VERSION 5.7 ;
  NOWIREEXTENSIONATPIN ON ;
  DIVIDERCHAR "/" ;
  BUSBITCHARS "[]" ;
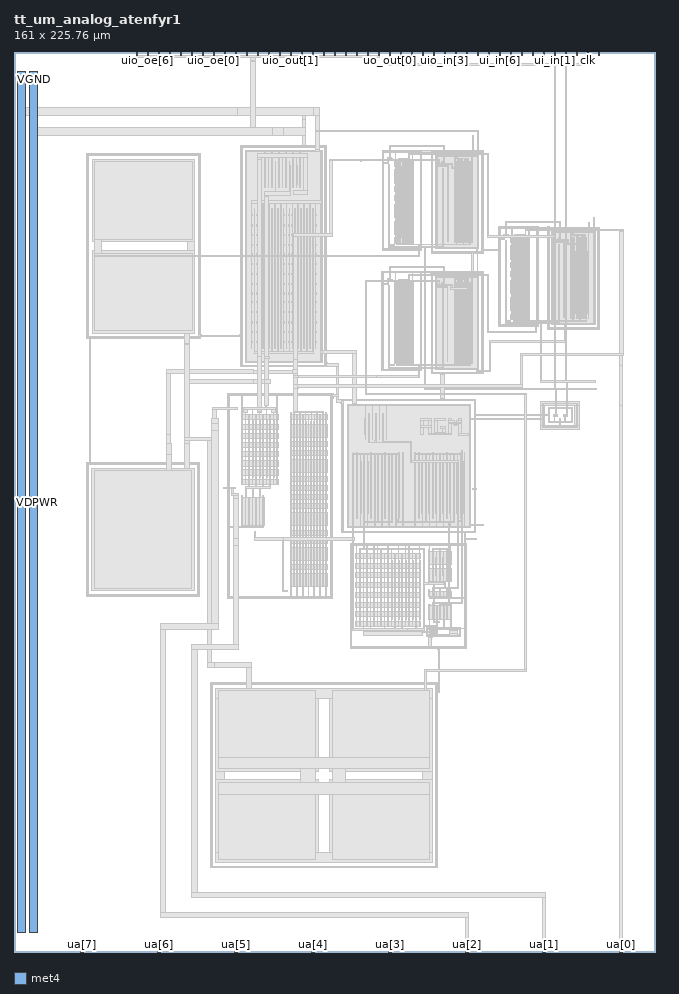
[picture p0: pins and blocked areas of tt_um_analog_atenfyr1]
MACRO tt_um_analog_atenfyr1
  CLASS BLOCK ;
  FOREIGN tt_um_analog_atenfyr1 ;
  ORIGIN 0.000 0.000 ;
  SIZE 161.000 BY 225.760 ;
  PIN VGND
    USE GROUND ;
    PORT
      LAYER met4 ;
        RECT 4.000 5.000 6.000 220.760 ;
    END
  END VGND
  PIN VDPWR
    USE POWER ;
    PORT
      LAYER met4 ;
        RECT 1.000 5.000 3.000 220.760 ;
    END
  END VDPWR
  PIN uo_out[7]
    ANTENNAGATEAREA 107.399994 ;
    ANTENNADIFFAREA 342.756805 ;
    PORT
      LAYER met4 ;
        RECT 74.830 224.760 75.130 225.760 ;
    END
  END uo_out[7]
  PIN uo_out[6]
    ANTENNAGATEAREA 107.399994 ;
    ANTENNADIFFAREA 342.756805 ;
    PORT
      LAYER met4 ;
        RECT 77.590 224.760 77.890 225.760 ;
    END
  END uo_out[6]
  PIN uo_out[5]
    ANTENNAGATEAREA 107.399994 ;
    ANTENNADIFFAREA 342.756805 ;
    PORT
      LAYER met4 ;
        RECT 80.350 224.760 80.650 225.760 ;
    END
  END uo_out[5]
  PIN uo_out[4]
    ANTENNAGATEAREA 107.399994 ;
    ANTENNADIFFAREA 342.756805 ;
    PORT
      LAYER met4 ;
        RECT 83.110 224.760 83.410 225.760 ;
    END
  END uo_out[4]
  PIN uo_out[3]
    ANTENNAGATEAREA 107.399994 ;
    ANTENNADIFFAREA 342.756805 ;
    PORT
      LAYER met4 ;
        RECT 85.870 224.760 86.170 225.760 ;
    END
  END uo_out[3]
  PIN uo_out[2]
    ANTENNAGATEAREA 107.399994 ;
    ANTENNADIFFAREA 342.756805 ;
    PORT
      LAYER met4 ;
        RECT 88.630 224.760 88.930 225.760 ;
    END
  END uo_out[2]
  PIN uo_out[1]
    ANTENNAGATEAREA 107.399994 ;
    ANTENNADIFFAREA 342.756805 ;
    PORT
      LAYER met4 ;
        RECT 91.390 224.760 91.690 225.760 ;
    END
  END uo_out[1]
  PIN uo_out[0]
    PORT
      LAYER met4 ;
        RECT 94.150 224.760 94.450 225.760 ;
    END
  END uo_out[0]
  PIN uio_out[7]
    ANTENNAGATEAREA 107.399994 ;
    ANTENNADIFFAREA 342.756805 ;
    PORT
      LAYER met4 ;
        RECT 52.750 224.760 53.050 225.760 ;
    END
  END uio_out[7]
  PIN uio_out[6]
    ANTENNAGATEAREA 107.399994 ;
    ANTENNADIFFAREA 342.756805 ;
    PORT
      LAYER met4 ;
        RECT 55.510 224.760 55.810 225.760 ;
    END
  END uio_out[6]
  PIN uio_out[5]
    ANTENNAGATEAREA 107.399994 ;
    ANTENNADIFFAREA 342.756805 ;
    PORT
      LAYER met4 ;
        RECT 58.270 224.760 58.570 225.760 ;
    END
  END uio_out[5]
  PIN uio_out[4]
    ANTENNAGATEAREA 107.399994 ;
    ANTENNADIFFAREA 342.756805 ;
    PORT
      LAYER met4 ;
        RECT 61.030 224.760 61.330 225.760 ;
    END
  END uio_out[4]
  PIN uio_out[3]
    ANTENNAGATEAREA 107.399994 ;
    ANTENNADIFFAREA 342.756805 ;
    PORT
      LAYER met4 ;
        RECT 63.790 224.760 64.090 225.760 ;
    END
  END uio_out[3]
  PIN uio_out[2]
    ANTENNAGATEAREA 107.399994 ;
    ANTENNADIFFAREA 342.756805 ;
    PORT
      LAYER met4 ;
        RECT 66.550 224.760 66.850 225.760 ;
    END
  END uio_out[2]
  PIN uio_out[1]
    ANTENNAGATEAREA 107.399994 ;
    ANTENNADIFFAREA 342.756805 ;
    PORT
      LAYER met4 ;
        RECT 69.310 224.760 69.610 225.760 ;
    END
  END uio_out[1]
  PIN uio_out[0]
    ANTENNAGATEAREA 107.399994 ;
    ANTENNADIFFAREA 342.756805 ;
    PORT
      LAYER met4 ;
        RECT 72.070 224.760 72.370 225.760 ;
    END
  END uio_out[0]
  PIN uio_oe[7]
    ANTENNAGATEAREA 107.399994 ;
    ANTENNADIFFAREA 342.756805 ;
    PORT
      LAYER met4 ;
        RECT 30.670 224.760 30.970 225.760 ;
    END
  END uio_oe[7]
  PIN uio_oe[6]
    ANTENNAGATEAREA 107.399994 ;
    ANTENNADIFFAREA 342.756805 ;
    PORT
      LAYER met4 ;
        RECT 33.430 224.760 33.730 225.760 ;
    END
  END uio_oe[6]
  PIN uio_oe[5]
    ANTENNAGATEAREA 107.399994 ;
    ANTENNADIFFAREA 342.756805 ;
    PORT
      LAYER met4 ;
        RECT 36.190 224.760 36.490 225.760 ;
    END
  END uio_oe[5]
  PIN uio_oe[4]
    ANTENNAGATEAREA 107.399994 ;
    ANTENNADIFFAREA 342.756805 ;
    PORT
      LAYER met4 ;
        RECT 38.950 224.760 39.250 225.760 ;
    END
  END uio_oe[4]
  PIN uio_oe[3]
    ANTENNAGATEAREA 107.399994 ;
    ANTENNADIFFAREA 342.756805 ;
    PORT
      LAYER met4 ;
        RECT 41.710 224.760 42.010 225.760 ;
    END
  END uio_oe[3]
  PIN uio_oe[2]
    ANTENNAGATEAREA 107.399994 ;
    ANTENNADIFFAREA 342.756805 ;
    PORT
      LAYER met4 ;
        RECT 44.470 224.760 44.770 225.760 ;
    END
  END uio_oe[2]
  PIN uio_oe[1]
    ANTENNAGATEAREA 107.399994 ;
    ANTENNADIFFAREA 342.756805 ;
    PORT
      LAYER met4 ;
        RECT 47.230 224.760 47.530 225.760 ;
    END
  END uio_oe[1]
  PIN uio_oe[0]
    ANTENNAGATEAREA 107.399994 ;
    ANTENNADIFFAREA 342.756805 ;
    PORT
      LAYER met4 ;
        RECT 49.990 224.760 50.290 225.760 ;
    END
  END uio_oe[0]
  PIN uio_in[7]
    PORT
      LAYER met4 ;
        RECT 96.910 224.760 97.210 225.760 ;
    END
  END uio_in[7]
  PIN uio_in[6]
    PORT
      LAYER met4 ;
        RECT 99.670 224.760 99.970 225.760 ;
    END
  END uio_in[6]
  PIN uio_in[5]
    PORT
      LAYER met4 ;
        RECT 102.430 224.760 102.730 225.760 ;
    END
  END uio_in[5]
  PIN uio_in[4]
    PORT
      LAYER met4 ;
        RECT 105.190 224.760 105.490 225.760 ;
    END
  END uio_in[4]
  PIN uio_in[3]
    PORT
      LAYER met4 ;
        RECT 107.950 224.760 108.250 225.760 ;
    END
  END uio_in[3]
  PIN uio_in[2]
    PORT
      LAYER met4 ;
        RECT 110.710 224.760 111.010 225.760 ;
    END
  END uio_in[2]
  PIN uio_in[1]
    PORT
      LAYER met4 ;
        RECT 113.470 224.760 113.770 225.760 ;
    END
  END uio_in[1]
  PIN uio_in[0]
    PORT
      LAYER met4 ;
        RECT 116.230 224.760 116.530 225.760 ;
    END
  END uio_in[0]
  PIN ui_in[7]
    PORT
      LAYER met4 ;
        RECT 118.990 224.760 119.290 225.760 ;
    END
  END ui_in[7]
  PIN ui_in[6]
    PORT
      LAYER met4 ;
        RECT 121.750 224.760 122.050 225.760 ;
    END
  END ui_in[6]
  PIN ui_in[5]
    PORT
      LAYER met4 ;
        RECT 124.510 224.760 124.810 225.760 ;
    END
  END ui_in[5]
  PIN ui_in[4]
    PORT
      LAYER met4 ;
        RECT 127.270 224.760 127.570 225.760 ;
    END
  END ui_in[4]
  PIN ui_in[3]
    PORT
      LAYER met4 ;
        RECT 130.030 224.760 130.330 225.760 ;
    END
  END ui_in[3]
  PIN ui_in[2]
    PORT
      LAYER met4 ;
        RECT 132.790 224.760 133.090 225.760 ;
    END
  END ui_in[2]
  PIN ui_in[1]
    ANTENNAGATEAREA 24.449999 ;
    ANTENNADIFFAREA 0.111300 ;
    PORT
      LAYER met4 ;
        RECT 135.550 224.760 135.850 225.760 ;
    END
  END ui_in[1]
  PIN ui_in[0]
    ANTENNAGATEAREA 12.224999 ;
    ANTENNADIFFAREA 0.111300 ;
    PORT
      LAYER met4 ;
        RECT 138.310 224.760 138.610 225.760 ;
    END
  END ui_in[0]
  PIN ua[7]
    PORT
      LAYER met4 ;
        RECT 16.570 0.000 17.470 1.000 ;
    END
  END ua[7]
  PIN ua[6]
    PORT
      LAYER met4 ;
        RECT 35.890 0.000 36.790 1.000 ;
    END
  END ua[6]
  PIN ua[5]
    PORT
      LAYER met4 ;
        RECT 55.210 0.000 56.110 1.000 ;
    END
  END ua[5]
  PIN ua[4]
    PORT
      LAYER met4 ;
        RECT 74.530 0.000 75.430 1.000 ;
    END
  END ua[4]
  PIN ua[3]
    PORT
      LAYER met4 ;
        RECT 93.850 0.000 94.750 1.000 ;
    END
  END ua[3]
  PIN ua[2]
    ANTENNAGATEAREA 19.199999 ;
    PORT
      LAYER met4 ;
        RECT 113.170 0.000 114.070 1.000 ;
    END
  END ua[2]
  PIN ua[1]
    ANTENNAGATEAREA 19.199999 ;
    PORT
      LAYER met4 ;
        RECT 132.490 0.000 133.390 1.000 ;
    END
  END ua[1]
  PIN ua[0]
    ANTENNADIFFAREA 130.199997 ;
    PORT
      LAYER met4 ;
        RECT 151.810 0.000 152.710 1.000 ;
    END
  END ua[0]
  PIN rst_n
    PORT
      LAYER met4 ;
        RECT 141.070 224.760 141.370 225.760 ;
    END
  END rst_n
  PIN ena
    PORT
      LAYER met4 ;
        RECT 146.590 224.760 146.890 225.760 ;
    END
  END ena
  PIN clk
    PORT
      LAYER met4 ;
        RECT 143.830 224.760 144.130 225.760 ;
    END
  END clk
  OBS
      LAYER pwell ;
        RECT 56.830 201.780 78.440 202.210 ;
        RECT 18.290 199.780 46.690 200.210 ;
        RECT 18.290 154.280 18.720 199.780 ;
        RECT 46.260 154.280 46.690 199.780 ;
        RECT 18.290 153.850 46.690 154.280 ;
        RECT 56.830 147.185 57.260 201.780 ;
      LAYER nwell ;
        RECT 57.950 147.875 77.320 201.090 ;
      LAYER pwell ;
        RECT 78.010 147.185 78.440 201.780 ;
        RECT 92.320 200.675 102.310 201.105 ;
        RECT 92.320 176.495 92.750 200.675 ;
        RECT 93.630 198.420 94.570 199.180 ;
        RECT 95.440 197.105 100.250 198.365 ;
        RECT 95.440 192.865 100.250 196.215 ;
        RECT 95.440 190.715 100.250 191.975 ;
        RECT 95.440 188.480 100.250 189.740 ;
        RECT 95.440 184.240 100.250 187.590 ;
        RECT 95.440 179.995 100.250 183.350 ;
        RECT 95.440 177.845 100.250 179.105 ;
        RECT 101.880 176.495 102.310 200.675 ;
        RECT 92.320 176.065 102.310 176.495 ;
        RECT 104.640 200.505 117.665 200.935 ;
        RECT 104.640 175.740 105.070 200.505 ;
      LAYER nwell ;
        RECT 105.760 176.430 116.565 199.815 ;
      LAYER pwell ;
        RECT 117.235 175.740 117.665 200.505 ;
        RECT 104.640 175.310 117.665 175.740 ;
        RECT 121.500 181.570 131.490 182.000 ;
        RECT 56.830 146.755 78.440 147.185 ;
        RECT 92.310 170.360 102.300 170.790 ;
        RECT 92.310 146.180 92.740 170.360 ;
        RECT 93.620 168.105 94.560 168.865 ;
        RECT 95.430 166.790 100.240 168.050 ;
        RECT 95.430 162.550 100.240 165.900 ;
        RECT 95.430 160.400 100.240 161.660 ;
        RECT 95.430 158.165 100.240 159.425 ;
        RECT 95.430 153.925 100.240 157.275 ;
        RECT 95.430 149.680 100.240 153.035 ;
        RECT 95.430 147.530 100.240 148.790 ;
        RECT 101.870 146.180 102.300 170.360 ;
        RECT 92.310 145.750 102.300 146.180 ;
        RECT 104.630 170.190 117.655 170.620 ;
        RECT 104.630 145.425 105.060 170.190 ;
      LAYER nwell ;
        RECT 105.750 146.115 116.555 169.500 ;
      LAYER pwell ;
        RECT 117.225 145.425 117.655 170.190 ;
        RECT 121.500 157.390 121.930 181.570 ;
        RECT 122.810 179.315 123.750 180.075 ;
        RECT 124.620 178.000 129.430 179.260 ;
        RECT 124.620 173.760 129.430 177.110 ;
        RECT 124.620 171.610 129.430 172.870 ;
        RECT 124.620 169.375 129.430 170.635 ;
        RECT 124.620 165.135 129.430 168.485 ;
        RECT 124.620 160.890 129.430 164.245 ;
        RECT 124.620 158.740 129.430 160.000 ;
        RECT 131.060 157.390 131.490 181.570 ;
        RECT 121.500 156.960 131.490 157.390 ;
        RECT 133.820 181.400 146.845 181.830 ;
        RECT 133.820 156.635 134.250 181.400 ;
      LAYER nwell ;
        RECT 134.940 157.325 145.745 180.710 ;
      LAYER pwell ;
        RECT 146.415 156.635 146.845 181.400 ;
        RECT 133.820 156.205 146.845 156.635 ;
        RECT 104.630 144.995 117.655 145.425 ;
        RECT 53.600 139.680 79.890 140.110 ;
        RECT 18.160 122.250 46.560 122.680 ;
        RECT 18.160 89.710 18.590 122.250 ;
        RECT 46.130 89.710 46.560 122.250 ;
        RECT 18.160 89.280 46.560 89.710 ;
        RECT 53.600 89.180 54.030 139.680 ;
        RECT 56.945 133.460 66.255 134.720 ;
        RECT 69.245 133.460 78.515 134.720 ;
        RECT 56.945 131.160 66.255 132.420 ;
        RECT 56.945 128.905 66.255 130.165 ;
        RECT 69.245 129.095 78.515 132.410 ;
        RECT 56.945 126.605 66.255 127.865 ;
        RECT 69.245 126.785 78.515 128.045 ;
        RECT 56.945 124.205 66.255 125.465 ;
        RECT 69.245 124.555 78.515 125.815 ;
        RECT 56.945 121.905 66.255 123.165 ;
        RECT 56.945 119.650 66.255 120.910 ;
        RECT 69.245 120.345 78.515 123.660 ;
        RECT 56.945 117.350 66.255 118.610 ;
        RECT 69.245 118.035 78.515 119.295 ;
        RECT 69.245 115.845 78.515 117.105 ;
        RECT 56.955 106.985 62.745 114.000 ;
        RECT 69.245 113.585 78.515 114.845 ;
        RECT 69.245 111.250 78.515 112.510 ;
        RECT 69.245 106.885 78.515 110.200 ;
        RECT 69.245 104.575 78.515 105.835 ;
        RECT 69.245 102.345 78.515 103.605 ;
        RECT 69.245 98.135 78.515 101.450 ;
        RECT 69.245 95.825 78.515 97.085 ;
        RECT 69.245 91.590 78.515 94.895 ;
        RECT 79.460 89.180 79.890 139.680 ;
        RECT 82.235 138.270 115.850 138.700 ;
        RECT 82.235 105.545 82.665 138.270 ;
      LAYER nwell ;
        RECT 83.535 106.415 114.550 137.400 ;
      LAYER pwell ;
        RECT 115.420 105.545 115.850 138.270 ;
      LAYER nwell ;
        RECT 132.015 137.130 141.815 138.190 ;
        RECT 132.015 132.190 133.105 137.130 ;
      LAYER pwell ;
        RECT 134.020 136.240 140.190 136.670 ;
        RECT 134.020 133.140 134.450 136.240 ;
        RECT 135.330 134.270 136.270 134.950 ;
        RECT 137.940 134.270 138.880 134.950 ;
        RECT 139.760 133.140 140.190 136.240 ;
        RECT 134.020 132.710 140.190 133.140 ;
      LAYER nwell ;
        RECT 140.705 132.190 141.815 137.130 ;
        RECT 132.015 131.130 141.815 132.190 ;
      LAYER pwell ;
        RECT 82.235 105.115 115.850 105.545 ;
        RECT 53.600 88.750 79.890 89.180 ;
        RECT 84.340 101.925 113.400 102.355 ;
        RECT 84.340 76.675 84.770 101.925 ;
        RECT 85.650 98.605 102.000 99.865 ;
        RECT 85.650 96.180 102.000 97.440 ;
        RECT 103.945 97.090 109.735 100.450 ;
        RECT 85.650 93.845 102.000 95.105 ;
        RECT 103.945 92.855 109.735 96.215 ;
        RECT 85.650 91.420 102.000 92.680 ;
        RECT 85.650 88.895 102.000 90.155 ;
        RECT 103.945 89.070 109.735 90.330 ;
        RECT 85.650 86.470 102.000 87.730 ;
        RECT 85.650 84.135 102.000 85.395 ;
        RECT 104.010 83.455 109.800 86.815 ;
        RECT 85.650 81.710 102.000 82.970 ;
        RECT 103.385 80.955 112.105 81.385 ;
        RECT 103.385 79.565 103.815 80.955 ;
        RECT 111.675 79.565 112.105 80.955 ;
        RECT 103.385 79.135 112.105 79.565 ;
        RECT 112.970 76.675 113.400 101.925 ;
        RECT 84.340 76.245 113.400 76.675 ;
        RECT 49.260 67.060 106.270 67.490 ;
        RECT 49.260 21.560 49.690 67.060 ;
        RECT 105.840 21.560 106.270 67.060 ;
        RECT 49.260 21.130 106.270 21.560 ;
      LAYER li1 ;
        RECT 72.295 202.080 73.215 202.730 ;
        RECT 56.960 201.910 78.310 202.080 ;
        RECT 18.420 199.910 46.560 200.080 ;
        RECT 18.420 154.150 18.590 199.910 ;
        RECT 46.390 154.790 46.560 199.910 ;
        RECT 56.960 154.790 57.130 201.910 ;
        RECT 75.680 200.910 76.570 201.550 ;
        RECT 46.390 154.460 46.950 154.790 ;
        RECT 56.585 154.460 57.130 154.790 ;
        RECT 46.390 154.150 46.560 154.460 ;
        RECT 18.420 153.980 46.560 154.150 ;
        RECT 18.970 153.475 19.300 153.980 ;
        RECT 56.960 147.055 57.130 154.460 ;
        RECT 58.130 200.740 77.140 200.910 ;
        RECT 58.130 148.225 58.300 200.740 ;
        RECT 62.875 191.690 63.045 200.740 ;
        RECT 63.395 199.240 64.285 199.570 ;
        RECT 63.755 191.690 63.925 199.240 ;
        RECT 64.635 191.690 64.805 200.740 ;
        RECT 65.515 191.690 65.685 198.175 ;
        RECT 66.395 191.690 66.565 200.740 ;
        RECT 66.915 199.240 67.805 199.570 ;
        RECT 67.275 191.690 67.445 199.240 ;
        RECT 68.155 191.690 68.325 200.740 ;
        RECT 69.035 191.690 69.205 198.175 ;
        RECT 69.915 191.690 70.085 200.740 ;
        RECT 70.435 199.240 71.325 199.570 ;
        RECT 70.795 191.690 70.965 199.240 ;
        RECT 71.675 191.690 71.845 200.740 ;
        RECT 70.150 189.930 70.320 190.980 ;
        RECT 76.970 188.485 77.140 200.740 ;
        RECT 59.520 187.705 77.140 188.485 ;
        RECT 59.520 151.455 59.690 187.705 ;
        RECT 60.250 150.685 60.420 186.510 ;
        RECT 60.980 151.455 61.150 187.705 ;
        RECT 61.710 150.685 61.880 186.510 ;
        RECT 62.440 151.455 62.610 187.705 ;
        RECT 63.170 150.685 63.340 186.510 ;
        RECT 63.900 151.455 64.070 187.705 ;
        RECT 64.630 150.685 64.800 186.510 ;
        RECT 65.360 151.455 65.530 187.705 ;
        RECT 66.090 150.685 66.260 186.510 ;
        RECT 66.820 151.455 66.990 187.705 ;
        RECT 67.550 150.685 67.720 186.510 ;
        RECT 68.280 151.455 68.450 187.705 ;
        RECT 69.010 150.685 69.180 186.510 ;
        RECT 69.740 151.455 69.910 187.705 ;
        RECT 70.470 150.685 70.640 186.510 ;
        RECT 71.200 151.455 71.370 187.705 ;
        RECT 71.930 150.685 72.100 186.510 ;
        RECT 72.660 151.455 72.830 187.705 ;
        RECT 73.390 150.685 73.560 186.510 ;
        RECT 74.120 151.455 74.290 187.705 ;
        RECT 74.850 150.685 75.020 186.510 ;
        RECT 75.580 151.455 75.750 187.705 ;
        RECT 60.250 150.015 75.020 150.685 ;
        RECT 76.970 150.930 77.140 187.705 ;
        RECT 76.970 150.040 77.715 150.930 ;
        RECT 63.930 148.915 64.100 149.245 ;
        RECT 70.145 149.225 71.160 150.015 ;
        RECT 76.970 148.225 77.140 150.040 ;
        RECT 58.130 148.055 77.140 148.225 ;
        RECT 78.140 147.970 78.310 201.910 ;
        RECT 92.450 200.805 102.390 200.975 ;
        RECT 92.450 198.025 92.620 200.805 ;
        RECT 94.230 199.050 94.400 199.570 ;
        RECT 93.800 198.025 93.970 199.050 ;
        RECT 94.230 198.880 94.980 199.050 ;
        RECT 94.230 198.550 94.400 198.880 ;
        RECT 92.450 197.820 93.970 198.025 ;
        RECT 92.450 176.365 92.620 197.820 ;
        RECT 94.075 197.170 94.245 197.500 ;
        RECT 95.610 177.975 95.780 200.805 ;
        RECT 99.050 199.120 99.220 199.495 ;
        RECT 96.470 198.940 99.220 199.120 ;
        RECT 96.040 177.580 96.210 198.235 ;
        RECT 96.470 177.975 96.640 198.940 ;
        RECT 96.900 177.975 97.070 198.745 ;
        RECT 97.330 177.975 97.500 198.940 ;
        RECT 97.760 177.580 97.930 198.235 ;
        RECT 98.190 177.975 98.360 198.940 ;
        RECT 98.620 177.975 98.790 198.745 ;
        RECT 99.050 177.975 99.220 198.940 ;
        RECT 99.480 177.580 99.650 198.235 ;
        RECT 99.910 177.975 100.080 200.805 ;
        RECT 102.010 200.645 102.390 200.805 ;
        RECT 104.560 200.805 105.060 200.975 ;
        RECT 115.015 200.805 115.185 201.445 ;
        RECT 95.060 177.375 95.390 177.545 ;
        RECT 96.040 177.365 101.525 177.580 ;
        RECT 102.010 176.365 102.180 200.645 ;
        RECT 104.560 200.635 117.535 200.805 ;
        RECT 92.450 176.195 102.180 176.365 ;
        RECT 104.770 175.610 104.940 200.635 ;
        RECT 106.275 200.135 109.055 200.305 ;
        RECT 116.195 199.635 116.365 200.220 ;
        RECT 105.940 199.465 116.365 199.635 ;
        RECT 105.940 197.285 106.110 199.465 ;
        RECT 107.330 197.285 107.500 198.285 ;
        RECT 105.940 197.105 107.500 197.285 ;
        RECT 107.760 197.285 107.930 198.770 ;
        RECT 105.940 176.780 106.110 197.105 ;
        RECT 107.760 197.055 108.845 197.285 ;
        RECT 108.675 196.955 108.845 197.055 ;
        RECT 107.550 196.295 107.720 196.625 ;
        RECT 108.675 178.350 108.845 178.680 ;
        RECT 110.505 177.960 110.675 199.465 ;
        RECT 110.925 198.955 114.115 199.140 ;
        RECT 110.935 177.580 111.105 198.235 ;
        RECT 111.365 177.960 111.535 198.955 ;
        RECT 111.795 177.960 111.965 198.745 ;
        RECT 112.225 177.960 112.395 198.955 ;
        RECT 112.655 177.580 112.825 198.235 ;
        RECT 113.085 177.960 113.255 198.955 ;
        RECT 113.515 177.960 113.690 198.745 ;
        RECT 113.945 177.960 114.115 198.955 ;
        RECT 114.375 177.580 114.545 198.235 ;
        RECT 114.805 177.960 114.975 199.465 ;
        RECT 106.820 177.365 114.545 177.580 ;
        RECT 116.195 176.780 116.365 199.465 ;
        RECT 105.940 176.610 116.365 176.780 ;
        RECT 116.075 176.350 116.245 176.610 ;
        RECT 117.365 176.285 117.535 200.635 ;
        RECT 121.630 181.700 131.570 181.870 ;
        RECT 121.630 178.920 121.800 181.700 ;
        RECT 123.410 179.945 123.580 180.465 ;
        RECT 122.980 178.920 123.150 179.945 ;
        RECT 123.410 179.775 124.160 179.945 ;
        RECT 123.410 179.445 123.580 179.775 ;
        RECT 121.630 178.715 123.150 178.920 ;
        RECT 121.630 176.310 121.800 178.715 ;
        RECT 123.255 178.065 123.425 178.395 ;
        RECT 117.365 175.955 117.705 176.285 ;
        RECT 121.460 175.980 121.800 176.310 ;
        RECT 109.810 175.610 110.700 175.815 ;
        RECT 117.365 175.610 117.535 175.955 ;
        RECT 104.770 175.440 117.535 175.610 ;
        RECT 114.865 175.035 115.035 175.440 ;
        RECT 92.440 170.490 102.380 170.660 ;
        RECT 92.440 167.710 92.610 170.490 ;
        RECT 94.220 168.735 94.390 169.255 ;
        RECT 93.790 167.710 93.960 168.735 ;
        RECT 94.220 168.565 94.970 168.735 ;
        RECT 94.220 168.235 94.390 168.565 ;
        RECT 92.440 167.505 93.960 167.710 ;
        RECT 78.140 147.055 78.645 147.970 ;
        RECT 56.960 146.920 78.645 147.055 ;
        RECT 56.960 146.885 78.310 146.920 ;
        RECT 92.440 146.050 92.610 167.505 ;
        RECT 94.065 166.855 94.235 167.185 ;
        RECT 95.600 147.660 95.770 170.490 ;
        RECT 99.040 168.805 99.210 169.180 ;
        RECT 96.460 168.625 99.210 168.805 ;
        RECT 96.030 147.265 96.200 167.920 ;
        RECT 96.460 147.660 96.630 168.625 ;
        RECT 96.890 147.660 97.060 168.430 ;
        RECT 97.320 147.660 97.490 168.625 ;
        RECT 97.750 147.265 97.920 167.920 ;
        RECT 98.180 147.660 98.350 168.625 ;
        RECT 98.610 147.660 98.780 168.430 ;
        RECT 99.040 147.660 99.210 168.625 ;
        RECT 99.470 147.265 99.640 167.920 ;
        RECT 99.900 147.660 100.070 170.490 ;
        RECT 102.000 170.330 102.380 170.490 ;
        RECT 104.550 170.490 105.050 170.660 ;
        RECT 115.005 170.490 115.175 171.130 ;
        RECT 95.050 147.060 95.380 147.230 ;
        RECT 96.030 147.050 101.515 147.265 ;
        RECT 102.000 146.050 102.170 170.330 ;
        RECT 104.550 170.320 117.525 170.490 ;
        RECT 59.705 145.100 70.110 145.990 ;
        RECT 92.440 145.880 102.170 146.050 ;
        RECT 104.760 145.295 104.930 170.320 ;
        RECT 106.265 169.820 109.045 169.990 ;
        RECT 116.185 169.320 116.355 169.905 ;
        RECT 105.930 169.150 116.355 169.320 ;
        RECT 105.930 166.970 106.100 169.150 ;
        RECT 107.320 166.970 107.490 167.970 ;
        RECT 105.930 166.790 107.490 166.970 ;
        RECT 107.750 166.970 107.920 168.455 ;
        RECT 105.930 146.465 106.100 166.790 ;
        RECT 107.750 166.740 108.835 166.970 ;
        RECT 108.665 166.640 108.835 166.740 ;
        RECT 107.540 165.980 107.710 166.310 ;
        RECT 108.665 148.035 108.835 148.365 ;
        RECT 110.495 147.645 110.665 169.150 ;
        RECT 110.915 168.640 114.105 168.825 ;
        RECT 110.925 147.265 111.095 167.920 ;
        RECT 111.355 147.645 111.525 168.640 ;
        RECT 111.785 147.645 111.955 168.430 ;
        RECT 112.215 147.645 112.385 168.640 ;
        RECT 112.645 147.265 112.815 167.920 ;
        RECT 113.075 147.645 113.245 168.640 ;
        RECT 113.505 147.645 113.680 168.430 ;
        RECT 113.935 147.645 114.105 168.640 ;
        RECT 114.365 147.265 114.535 167.920 ;
        RECT 114.795 147.645 114.965 169.150 ;
        RECT 106.810 147.050 114.535 147.265 ;
        RECT 116.185 146.465 116.355 169.150 ;
        RECT 105.930 146.295 116.355 146.465 ;
        RECT 116.065 145.995 116.235 146.295 ;
        RECT 117.355 145.295 117.525 170.320 ;
        RECT 121.630 157.260 121.800 175.980 ;
        RECT 124.790 158.870 124.960 181.700 ;
        RECT 128.230 180.015 128.400 180.390 ;
        RECT 125.650 179.835 128.400 180.015 ;
        RECT 125.220 158.475 125.390 179.130 ;
        RECT 125.650 158.870 125.820 179.835 ;
        RECT 126.080 158.870 126.250 179.640 ;
        RECT 126.510 158.870 126.680 179.835 ;
        RECT 126.940 158.475 127.110 179.130 ;
        RECT 127.370 158.870 127.540 179.835 ;
        RECT 127.800 158.870 127.970 179.640 ;
        RECT 128.230 158.870 128.400 179.835 ;
        RECT 128.660 158.475 128.830 179.130 ;
        RECT 129.090 158.870 129.260 181.700 ;
        RECT 131.190 181.540 131.570 181.700 ;
        RECT 133.740 181.700 134.240 181.870 ;
        RECT 144.195 181.700 144.365 182.340 ;
        RECT 124.240 158.270 124.570 158.440 ;
        RECT 125.220 158.260 130.705 158.475 ;
        RECT 131.190 157.260 131.360 181.540 ;
        RECT 133.740 181.530 146.715 181.700 ;
        RECT 121.630 157.090 131.360 157.260 ;
        RECT 133.950 156.505 134.120 181.530 ;
        RECT 135.455 181.030 138.235 181.200 ;
        RECT 145.375 180.530 145.545 181.115 ;
        RECT 135.120 180.360 145.545 180.530 ;
        RECT 135.120 178.180 135.290 180.360 ;
        RECT 136.510 178.180 136.680 179.180 ;
        RECT 135.120 178.000 136.680 178.180 ;
        RECT 136.940 178.180 137.110 179.665 ;
        RECT 135.120 157.675 135.290 178.000 ;
        RECT 136.940 177.950 138.025 178.180 ;
        RECT 137.855 177.850 138.025 177.950 ;
        RECT 136.730 177.190 136.900 177.520 ;
        RECT 137.855 159.245 138.025 159.575 ;
        RECT 139.685 158.855 139.855 180.360 ;
        RECT 140.105 179.850 143.295 180.035 ;
        RECT 140.115 158.475 140.285 179.130 ;
        RECT 140.545 158.855 140.715 179.850 ;
        RECT 140.975 158.855 141.145 179.640 ;
        RECT 141.405 158.855 141.575 179.850 ;
        RECT 141.835 158.475 142.005 179.130 ;
        RECT 142.265 158.855 142.435 179.850 ;
        RECT 142.695 158.855 142.870 179.640 ;
        RECT 143.125 158.855 143.295 179.850 ;
        RECT 143.555 158.475 143.725 179.130 ;
        RECT 143.985 158.855 144.155 180.360 ;
        RECT 136.000 158.260 143.725 158.475 ;
        RECT 145.375 157.675 145.545 180.360 ;
        RECT 135.120 157.505 145.545 157.675 ;
        RECT 138.115 157.175 138.285 157.505 ;
        RECT 146.545 156.505 146.715 181.530 ;
        RECT 133.950 156.335 146.715 156.505 ;
        RECT 104.760 145.125 117.525 145.295 ;
        RECT 107.095 144.535 107.985 145.125 ;
        RECT 59.705 142.530 64.310 143.500 ;
        RECT 105.630 141.095 109.070 141.425 ;
        RECT 53.730 139.810 80.100 139.980 ;
        RECT 138.510 139.890 138.740 142.485 ;
        RECT 18.970 122.550 19.300 122.980 ;
        RECT 18.290 122.380 46.430 122.550 ;
        RECT 18.290 89.580 18.460 122.380 ;
        RECT 46.260 89.580 46.430 122.380 ;
        RECT 18.290 89.410 46.430 89.580 ;
        RECT 53.730 106.840 53.900 139.810 ;
        RECT 55.740 136.140 55.910 136.470 ;
        RECT 57.115 117.480 57.285 139.810 ;
        RECT 62.895 136.975 63.785 137.305 ;
        RECT 63.210 136.350 63.445 136.975 ;
        RECT 59.755 136.100 63.445 136.350 ;
        RECT 57.635 135.370 58.525 135.700 ;
        RECT 57.995 117.480 58.165 135.370 ;
        RECT 58.875 117.480 59.045 134.590 ;
        RECT 59.755 117.480 59.925 136.100 ;
        RECT 61.155 135.370 62.045 135.700 ;
        RECT 60.635 117.480 60.805 134.590 ;
        RECT 61.515 117.480 61.685 135.370 ;
        RECT 62.395 117.480 62.565 134.590 ;
        RECT 63.275 117.480 63.445 136.100 ;
        RECT 64.675 135.370 65.565 135.700 ;
        RECT 64.155 117.480 64.325 134.590 ;
        RECT 65.035 117.480 65.205 135.370 ;
        RECT 65.915 117.480 66.085 139.810 ;
        RECT 79.590 139.300 80.100 139.810 ;
        RECT 70.145 135.505 71.160 135.940 ;
        RECT 70.145 135.330 77.615 135.505 ;
        RECT 55.460 116.305 55.630 116.635 ;
        RECT 53.730 106.510 54.360 106.840 ;
        RECT 57.125 106.510 57.295 114.480 ;
        RECT 58.005 107.115 58.175 114.615 ;
        RECT 58.885 106.510 59.055 113.870 ;
        RECT 59.765 107.115 59.935 114.615 ;
        RECT 60.645 106.510 60.815 113.870 ;
        RECT 61.525 107.115 61.695 114.615 ;
        RECT 62.405 106.510 62.575 114.480 ;
        RECT 53.730 89.050 53.900 106.510 ;
        RECT 60.325 105.165 60.495 105.495 ;
        RECT 69.415 91.720 69.585 135.220 ;
        RECT 70.145 91.720 70.315 135.330 ;
        RECT 70.875 91.720 71.045 134.590 ;
        RECT 71.605 91.720 71.775 135.330 ;
        RECT 72.335 91.720 72.505 134.590 ;
        RECT 73.065 91.720 73.235 135.330 ;
        RECT 73.795 91.720 73.965 134.590 ;
        RECT 74.525 91.720 74.695 135.330 ;
        RECT 75.255 91.720 75.425 134.590 ;
        RECT 75.985 91.720 76.155 135.330 ;
        RECT 76.715 91.720 76.885 134.590 ;
        RECT 77.445 91.720 77.615 135.330 ;
        RECT 78.175 91.720 78.345 135.220 ;
        RECT 68.240 90.375 68.410 90.705 ;
        RECT 69.385 89.050 69.615 89.975 ;
        RECT 70.845 89.050 71.075 89.975 ;
        RECT 72.305 89.050 72.535 89.975 ;
        RECT 73.765 89.050 73.995 89.975 ;
        RECT 75.225 89.050 75.455 89.975 ;
        RECT 76.685 89.050 76.915 89.975 ;
        RECT 78.145 89.050 78.375 89.975 ;
        RECT 79.590 89.050 79.760 139.300 ;
        RECT 79.930 138.930 80.100 139.300 ;
        RECT 107.095 138.570 107.985 139.120 ;
        RECT 82.015 138.400 115.720 138.570 ;
        RECT 82.015 137.520 82.535 138.400 ;
        RECT 82.365 105.415 82.535 137.520 ;
        RECT 85.040 137.220 85.930 137.900 ;
        RECT 83.715 137.050 114.370 137.220 ;
        RECT 83.715 106.765 83.885 137.050 ;
        RECT 88.075 128.480 88.245 137.050 ;
        RECT 88.955 127.915 89.125 135.205 ;
        RECT 89.835 128.480 90.005 137.050 ;
        RECT 90.715 128.245 90.885 135.205 ;
        RECT 91.595 128.480 91.765 137.050 ;
        RECT 90.490 127.915 90.885 128.245 ;
        RECT 92.475 127.915 92.645 135.205 ;
        RECT 93.355 128.480 93.525 137.050 ;
        RECT 114.200 133.865 114.370 137.050 ;
        RECT 115.550 134.915 115.720 138.400 ;
        RECT 132.540 137.540 141.230 137.710 ;
        RECT 115.550 134.585 116.190 134.915 ;
        RECT 114.200 133.535 114.795 133.865 ;
        RECT 114.200 129.955 114.370 133.535 ;
        RECT 113.735 129.625 114.370 129.955 ;
        RECT 88.955 127.725 93.210 127.915 ;
        RECT 85.105 106.765 85.275 125.290 ;
        RECT 85.985 108.620 86.155 125.185 ;
        RECT 86.865 106.765 87.035 124.440 ;
        RECT 87.745 107.695 87.915 124.440 ;
        RECT 88.625 106.765 88.795 124.440 ;
        RECT 89.505 108.620 89.675 125.185 ;
        RECT 90.385 106.765 90.555 124.440 ;
        RECT 91.265 107.695 91.435 124.440 ;
        RECT 92.145 106.765 92.315 124.440 ;
        RECT 93.025 108.620 93.195 125.185 ;
        RECT 93.905 106.765 94.075 124.440 ;
        RECT 94.785 107.695 94.955 124.440 ;
        RECT 95.665 106.765 95.835 124.440 ;
        RECT 96.545 108.620 96.715 125.185 ;
        RECT 96.240 108.105 96.410 108.435 ;
        RECT 97.425 106.765 97.595 125.290 ;
        RECT 100.585 106.765 100.755 125.290 ;
        RECT 101.465 108.620 101.635 125.185 ;
        RECT 102.345 106.765 102.515 124.440 ;
        RECT 103.225 107.695 103.395 124.440 ;
        RECT 104.105 106.765 104.275 124.440 ;
        RECT 104.985 108.620 105.155 125.185 ;
        RECT 105.865 106.765 106.035 124.440 ;
        RECT 106.745 107.695 106.915 124.440 ;
        RECT 107.625 106.765 107.795 124.440 ;
        RECT 108.505 108.620 108.675 125.185 ;
        RECT 109.385 106.765 109.555 124.440 ;
        RECT 110.265 107.695 110.435 124.440 ;
        RECT 111.145 106.765 111.315 124.440 ;
        RECT 112.025 108.620 112.195 125.185 ;
        RECT 111.725 108.015 111.895 108.345 ;
        RECT 112.905 106.765 113.075 125.290 ;
        RECT 114.200 107.145 114.370 129.625 ;
        RECT 115.550 116.315 115.720 134.585 ;
        RECT 132.540 133.865 132.710 137.540 ;
        RECT 134.150 136.370 140.060 136.540 ;
        RECT 134.150 134.915 134.320 136.370 ;
        RECT 133.740 134.585 134.320 134.915 ;
        RECT 132.110 133.535 132.710 133.865 ;
        RECT 132.540 131.840 132.710 133.535 ;
        RECT 134.150 133.010 134.320 134.585 ;
        RECT 135.500 133.010 135.670 134.820 ;
        RECT 135.930 134.400 136.100 135.370 ;
        RECT 136.805 133.470 136.975 133.800 ;
        RECT 138.110 133.010 138.280 134.820 ;
        RECT 138.540 134.400 138.710 135.370 ;
        RECT 139.890 133.010 140.060 136.370 ;
        RECT 134.150 132.840 140.060 133.010 ;
        RECT 136.735 131.840 137.065 132.430 ;
        RECT 141.060 131.840 141.230 137.540 ;
        RECT 132.540 131.670 141.230 131.840 ;
        RECT 115.045 115.985 115.935 116.315 ;
        RECT 114.200 106.915 114.840 107.145 ;
        RECT 114.200 106.765 114.370 106.915 ;
        RECT 83.715 106.595 114.370 106.765 ;
        RECT 115.550 105.415 115.720 115.985 ;
        RECT 82.365 105.245 115.720 105.415 ;
        RECT 112.995 104.915 113.225 105.245 ;
        RECT 112.995 102.225 113.230 102.555 ;
        RECT 53.730 88.880 79.760 89.050 ;
        RECT 84.470 102.055 113.270 102.225 ;
        RECT 84.470 76.545 84.640 102.055 ;
        RECT 85.820 81.840 85.990 102.055 ;
        RECT 86.700 81.840 86.870 101.210 ;
        RECT 87.580 80.315 87.750 99.735 ;
        RECT 88.460 81.840 88.630 102.055 ;
        RECT 89.340 81.085 89.510 99.735 ;
        RECT 90.220 81.840 90.390 102.055 ;
        RECT 91.100 81.840 91.270 102.055 ;
        RECT 91.980 81.840 92.150 101.210 ;
        RECT 89.310 80.795 89.540 81.085 ;
        RECT 89.340 80.775 89.510 80.795 ;
        RECT 92.860 80.315 93.030 99.735 ;
        RECT 93.740 81.840 93.910 102.055 ;
        RECT 94.620 81.840 94.790 101.210 ;
        RECT 95.500 80.315 95.670 99.735 ;
        RECT 96.380 81.840 96.550 102.055 ;
        RECT 97.260 81.085 97.430 99.735 ;
        RECT 98.140 81.840 98.310 102.055 ;
        RECT 99.020 81.840 99.190 102.055 ;
        RECT 99.900 81.840 100.070 101.210 ;
        RECT 97.225 80.795 98.410 81.085 ;
        RECT 97.260 80.775 97.430 80.795 ;
        RECT 100.780 80.315 100.950 99.735 ;
        RECT 101.660 81.840 101.830 102.055 ;
        RECT 104.115 100.920 104.285 102.055 ;
        RECT 104.065 100.590 104.335 100.920 ;
        RECT 104.995 100.880 105.170 101.210 ;
        RECT 104.115 92.985 104.285 100.590 ;
        RECT 104.995 92.860 105.165 100.880 ;
        RECT 105.875 92.265 106.045 100.320 ;
        RECT 106.755 92.835 106.925 101.210 ;
        RECT 107.635 92.265 107.805 100.320 ;
        RECT 108.515 92.835 108.685 101.210 ;
        RECT 109.395 100.920 109.565 102.055 ;
        RECT 109.345 100.590 109.615 100.920 ;
        RECT 109.395 92.855 109.565 100.590 ;
        RECT 108.075 91.395 108.345 92.605 ;
        RECT 104.995 91.215 110.280 91.395 ;
        RECT 104.065 90.600 104.340 90.930 ;
        RECT 104.115 88.865 104.285 90.600 ;
        RECT 104.995 89.200 105.165 91.215 ;
        RECT 105.875 88.865 106.045 90.200 ;
        RECT 106.755 89.200 106.925 91.215 ;
        RECT 107.635 88.865 107.805 90.200 ;
        RECT 108.515 89.200 108.685 91.215 ;
        RECT 109.345 90.600 109.615 90.930 ;
        RECT 109.395 88.865 109.565 90.600 ;
        RECT 113.100 88.865 113.270 102.055 ;
        RECT 104.115 88.675 113.270 88.865 ;
        RECT 105.270 88.065 105.440 88.395 ;
        RECT 105.060 87.540 110.550 87.730 ;
        RECT 104.050 86.935 104.400 87.265 ;
        RECT 104.180 81.255 104.350 86.935 ;
        RECT 105.060 83.585 105.230 87.540 ;
        RECT 105.440 81.640 105.610 81.970 ;
        RECT 105.940 81.255 106.110 86.685 ;
        RECT 106.820 83.585 106.990 87.260 ;
        RECT 106.345 82.650 106.515 82.980 ;
        RECT 107.700 81.255 107.870 86.685 ;
        RECT 108.580 83.585 108.750 87.540 ;
        RECT 109.410 86.935 109.680 87.265 ;
        RECT 109.460 81.255 109.630 86.935 ;
        RECT 113.100 81.255 113.270 88.675 ;
        RECT 103.515 81.085 113.270 81.255 ;
        RECT 87.580 79.465 102.595 80.315 ;
        RECT 103.515 79.435 103.685 81.085 ;
        RECT 104.165 79.915 106.325 80.605 ;
        RECT 109.165 79.435 111.325 80.605 ;
        RECT 111.805 79.435 111.975 81.085 ;
        RECT 103.515 79.265 111.975 79.435 ;
        RECT 104.090 78.875 104.945 79.265 ;
        RECT 104.090 76.545 104.650 78.875 ;
        RECT 113.100 76.545 113.270 81.085 ;
        RECT 84.470 76.375 113.270 76.545 ;
        RECT 106.340 75.865 106.670 76.375 ;
        RECT 49.390 67.190 106.140 67.360 ;
        RECT 49.390 21.430 49.560 67.190 ;
        RECT 105.970 65.420 106.140 67.190 ;
        RECT 105.970 65.090 106.575 65.420 ;
        RECT 105.970 21.430 106.140 65.090 ;
        RECT 49.390 21.260 106.140 21.430 ;
      LAYER met1 ;
        RECT 72.300 208.730 73.245 211.505 ;
        RECT 74.870 209.760 76.600 211.745 ;
        RECT 72.295 206.880 73.245 208.730 ;
        RECT 67.275 204.900 73.245 206.880 ;
        RECT 72.295 202.410 73.245 204.900 ;
        RECT 75.650 206.155 76.600 209.760 ;
        RECT 75.650 205.850 116.395 206.155 ;
        RECT 75.650 201.240 76.600 205.850 ;
        RECT 116.165 204.830 116.395 205.850 ;
        RECT 94.200 202.010 107.960 202.290 ;
        RECT 61.125 199.240 73.680 200.180 ;
        RECT 94.200 199.260 94.430 202.010 ;
        RECT 102.190 200.665 104.760 200.955 ;
        RECT 99.020 200.080 106.585 200.375 ;
        RECT 61.125 198.385 62.075 199.240 ;
        RECT 62.845 192.500 63.075 197.365 ;
        RECT 63.725 192.500 63.955 197.365 ;
        RECT 64.605 192.500 64.835 197.365 ;
        RECT 65.485 190.875 65.715 197.365 ;
        RECT 66.365 192.500 66.595 197.365 ;
        RECT 67.245 192.500 67.475 197.365 ;
        RECT 68.125 192.500 68.355 197.365 ;
        RECT 69.005 190.875 69.235 197.365 ;
        RECT 69.885 192.500 70.115 197.365 ;
        RECT 70.765 192.500 70.995 197.365 ;
        RECT 71.645 192.500 71.875 197.365 ;
        RECT 72.660 191.005 73.680 199.240 ;
        RECT 99.020 199.185 99.250 200.080 ;
        RECT 86.975 198.725 87.235 198.730 ;
        RECT 86.975 198.435 106.695 198.725 ;
        RECT 107.730 198.460 107.960 202.010 ;
        RECT 114.985 201.135 115.215 204.810 ;
        RECT 116.165 203.410 116.400 204.830 ;
        RECT 108.745 200.100 111.495 200.335 ;
        RECT 110.945 200.015 111.495 200.100 ;
        RECT 110.945 198.925 111.235 200.015 ;
        RECT 116.165 199.910 116.395 203.410 ;
        RECT 86.975 198.410 87.235 198.435 ;
        RECT 106.365 197.840 106.695 198.435 ;
        RECT 106.365 197.540 109.910 197.840 ;
        RECT 62.865 189.825 69.235 190.875 ;
        RECT 70.050 189.910 73.680 191.005 ;
        RECT 62.865 189.205 63.815 189.825 ;
        RECT 59.490 184.735 59.720 185.025 ;
        RECT 60.220 184.735 60.450 185.025 ;
        RECT 60.950 184.735 61.180 185.025 ;
        RECT 61.680 184.735 61.910 185.025 ;
        RECT 62.410 184.735 62.640 185.025 ;
        RECT 63.140 184.735 63.370 185.025 ;
        RECT 63.870 184.735 64.100 185.025 ;
        RECT 64.600 184.735 64.830 185.025 ;
        RECT 65.330 184.735 65.560 185.025 ;
        RECT 66.060 184.735 66.290 185.025 ;
        RECT 66.790 184.735 67.020 185.025 ;
        RECT 67.520 184.735 67.750 185.025 ;
        RECT 68.250 184.735 68.480 185.025 ;
        RECT 68.980 184.735 69.210 185.025 ;
        RECT 69.710 184.735 69.940 185.025 ;
        RECT 70.440 184.735 70.670 185.025 ;
        RECT 71.170 184.735 71.400 185.025 ;
        RECT 71.900 184.735 72.130 185.025 ;
        RECT 72.630 184.735 72.860 185.025 ;
        RECT 73.360 184.735 73.590 185.025 ;
        RECT 74.090 184.735 74.320 185.025 ;
        RECT 74.820 184.735 75.050 185.025 ;
        RECT 75.550 184.735 75.780 185.025 ;
        RECT 59.520 182.385 59.690 184.735 ;
        RECT 60.250 182.385 60.420 184.735 ;
        RECT 60.980 182.385 61.150 184.735 ;
        RECT 61.710 182.385 61.880 184.735 ;
        RECT 62.440 182.385 62.610 184.735 ;
        RECT 63.170 182.385 63.340 184.735 ;
        RECT 63.900 182.385 64.070 184.735 ;
        RECT 64.630 182.385 64.800 184.735 ;
        RECT 65.360 182.385 65.530 184.735 ;
        RECT 66.090 182.385 66.260 184.735 ;
        RECT 66.820 182.385 66.990 184.735 ;
        RECT 67.550 182.385 67.720 184.735 ;
        RECT 68.280 182.385 68.450 184.735 ;
        RECT 69.010 182.385 69.180 184.735 ;
        RECT 69.740 182.385 69.910 184.735 ;
        RECT 70.470 182.385 70.640 184.735 ;
        RECT 71.200 182.385 71.370 184.735 ;
        RECT 71.930 182.385 72.100 184.735 ;
        RECT 72.660 182.385 72.830 184.735 ;
        RECT 73.390 182.385 73.560 184.735 ;
        RECT 74.120 182.385 74.290 184.735 ;
        RECT 74.850 182.385 75.020 184.735 ;
        RECT 75.580 182.385 75.750 184.735 ;
        RECT 59.490 182.095 59.720 182.385 ;
        RECT 60.220 182.095 60.450 182.385 ;
        RECT 60.950 182.095 61.180 182.385 ;
        RECT 61.680 182.095 61.910 182.385 ;
        RECT 62.410 182.095 62.640 182.385 ;
        RECT 63.140 182.095 63.370 182.385 ;
        RECT 63.870 182.095 64.100 182.385 ;
        RECT 64.600 182.095 64.830 182.385 ;
        RECT 65.330 182.095 65.560 182.385 ;
        RECT 66.060 182.095 66.290 182.385 ;
        RECT 66.790 182.095 67.020 182.385 ;
        RECT 67.520 182.095 67.750 182.385 ;
        RECT 68.250 182.095 68.480 182.385 ;
        RECT 68.980 182.095 69.210 182.385 ;
        RECT 69.710 182.095 69.940 182.385 ;
        RECT 70.440 182.095 70.670 182.385 ;
        RECT 71.170 182.095 71.400 182.385 ;
        RECT 71.900 182.095 72.130 182.385 ;
        RECT 72.630 182.095 72.860 182.385 ;
        RECT 73.360 182.095 73.590 182.385 ;
        RECT 74.090 182.095 74.320 182.385 ;
        RECT 74.820 182.095 75.050 182.385 ;
        RECT 75.550 182.095 75.780 182.385 ;
        RECT 59.520 179.965 59.690 182.095 ;
        RECT 60.250 179.965 60.420 182.095 ;
        RECT 60.980 179.965 61.150 182.095 ;
        RECT 61.710 179.965 61.880 182.095 ;
        RECT 62.440 179.965 62.610 182.095 ;
        RECT 63.170 179.965 63.340 182.095 ;
        RECT 63.900 179.965 64.070 182.095 ;
        RECT 64.630 179.965 64.800 182.095 ;
        RECT 65.360 179.965 65.530 182.095 ;
        RECT 66.090 179.965 66.260 182.095 ;
        RECT 66.820 179.965 66.990 182.095 ;
        RECT 67.550 179.965 67.720 182.095 ;
        RECT 68.280 179.965 68.450 182.095 ;
        RECT 69.010 179.965 69.180 182.095 ;
        RECT 69.740 179.965 69.910 182.095 ;
        RECT 70.470 179.965 70.640 182.095 ;
        RECT 71.200 179.965 71.370 182.095 ;
        RECT 71.930 179.965 72.100 182.095 ;
        RECT 72.660 179.965 72.830 182.095 ;
        RECT 73.390 179.965 73.560 182.095 ;
        RECT 74.120 179.965 74.290 182.095 ;
        RECT 74.850 179.965 75.020 182.095 ;
        RECT 75.580 179.965 75.750 182.095 ;
        RECT 59.490 179.675 59.720 179.965 ;
        RECT 60.220 179.675 60.450 179.965 ;
        RECT 60.950 179.675 61.180 179.965 ;
        RECT 61.680 179.675 61.910 179.965 ;
        RECT 62.410 179.675 62.640 179.965 ;
        RECT 63.140 179.675 63.370 179.965 ;
        RECT 63.870 179.675 64.100 179.965 ;
        RECT 64.600 179.675 64.830 179.965 ;
        RECT 65.330 179.675 65.560 179.965 ;
        RECT 66.060 179.675 66.290 179.965 ;
        RECT 66.790 179.675 67.020 179.965 ;
        RECT 67.520 179.675 67.750 179.965 ;
        RECT 68.250 179.675 68.480 179.965 ;
        RECT 68.980 179.675 69.210 179.965 ;
        RECT 69.710 179.675 69.940 179.965 ;
        RECT 70.440 179.675 70.670 179.965 ;
        RECT 71.170 179.675 71.400 179.965 ;
        RECT 71.900 179.675 72.130 179.965 ;
        RECT 72.630 179.675 72.860 179.965 ;
        RECT 73.360 179.675 73.590 179.965 ;
        RECT 74.090 179.675 74.320 179.965 ;
        RECT 74.820 179.675 75.050 179.965 ;
        RECT 75.550 179.675 75.780 179.965 ;
        RECT 59.520 177.510 59.690 179.675 ;
        RECT 60.250 177.510 60.420 179.675 ;
        RECT 60.980 177.510 61.150 179.675 ;
        RECT 61.710 177.510 61.880 179.675 ;
        RECT 62.440 177.510 62.610 179.675 ;
        RECT 63.170 177.510 63.340 179.675 ;
        RECT 63.900 177.510 64.070 179.675 ;
        RECT 64.630 177.510 64.800 179.675 ;
        RECT 65.360 177.510 65.530 179.675 ;
        RECT 66.090 177.510 66.260 179.675 ;
        RECT 66.820 177.510 66.990 179.675 ;
        RECT 67.550 177.510 67.720 179.675 ;
        RECT 68.280 177.510 68.450 179.675 ;
        RECT 69.010 177.510 69.180 179.675 ;
        RECT 69.740 177.510 69.910 179.675 ;
        RECT 70.470 177.510 70.640 179.675 ;
        RECT 71.200 177.510 71.370 179.675 ;
        RECT 71.930 177.510 72.100 179.675 ;
        RECT 72.660 177.510 72.830 179.675 ;
        RECT 73.390 177.510 73.560 179.675 ;
        RECT 74.120 177.510 74.290 179.675 ;
        RECT 74.850 177.510 75.020 179.675 ;
        RECT 75.580 177.510 75.750 179.675 ;
        RECT 94.045 177.575 94.275 197.480 ;
        RECT 95.580 179.350 95.810 196.750 ;
        RECT 96.010 179.350 96.240 196.750 ;
        RECT 96.440 179.350 96.670 196.750 ;
        RECT 96.870 179.350 97.100 196.750 ;
        RECT 97.300 179.350 97.530 196.750 ;
        RECT 97.730 179.350 97.960 196.750 ;
        RECT 98.160 179.350 98.390 196.750 ;
        RECT 98.590 179.350 98.820 196.750 ;
        RECT 99.020 179.350 99.250 196.750 ;
        RECT 99.450 179.350 99.680 196.750 ;
        RECT 99.880 179.350 100.110 196.750 ;
        RECT 59.490 177.220 59.720 177.510 ;
        RECT 60.220 177.220 60.450 177.510 ;
        RECT 60.950 177.220 61.180 177.510 ;
        RECT 61.680 177.220 61.910 177.510 ;
        RECT 62.410 177.220 62.640 177.510 ;
        RECT 63.140 177.220 63.370 177.510 ;
        RECT 63.870 177.220 64.100 177.510 ;
        RECT 64.600 177.220 64.830 177.510 ;
        RECT 65.330 177.220 65.560 177.510 ;
        RECT 66.060 177.220 66.290 177.510 ;
        RECT 66.790 177.220 67.020 177.510 ;
        RECT 67.520 177.220 67.750 177.510 ;
        RECT 68.250 177.220 68.480 177.510 ;
        RECT 68.980 177.220 69.210 177.510 ;
        RECT 69.710 177.220 69.940 177.510 ;
        RECT 70.440 177.220 70.670 177.510 ;
        RECT 71.170 177.220 71.400 177.510 ;
        RECT 71.900 177.220 72.130 177.510 ;
        RECT 72.630 177.220 72.860 177.510 ;
        RECT 73.360 177.220 73.590 177.510 ;
        RECT 74.090 177.220 74.320 177.510 ;
        RECT 74.820 177.220 75.050 177.510 ;
        RECT 75.550 177.220 75.780 177.510 ;
        RECT 94.045 177.345 95.370 177.575 ;
        RECT 101.215 177.360 107.130 177.590 ;
        RECT 59.520 175.255 59.690 177.220 ;
        RECT 60.250 175.255 60.420 177.220 ;
        RECT 60.980 175.255 61.150 177.220 ;
        RECT 61.710 175.255 61.880 177.220 ;
        RECT 62.440 175.255 62.610 177.220 ;
        RECT 63.170 175.255 63.340 177.220 ;
        RECT 63.900 175.255 64.070 177.220 ;
        RECT 64.630 175.255 64.800 177.220 ;
        RECT 65.360 175.255 65.530 177.220 ;
        RECT 66.090 175.255 66.260 177.220 ;
        RECT 66.820 175.255 66.990 177.220 ;
        RECT 67.550 175.255 67.720 177.220 ;
        RECT 68.280 175.255 68.450 177.220 ;
        RECT 69.010 175.255 69.180 177.220 ;
        RECT 69.740 175.255 69.910 177.220 ;
        RECT 70.470 175.255 70.640 177.220 ;
        RECT 71.200 175.255 71.370 177.220 ;
        RECT 71.930 175.255 72.100 177.220 ;
        RECT 72.660 175.255 72.830 177.220 ;
        RECT 73.390 175.255 73.560 177.220 ;
        RECT 74.120 175.255 74.290 177.220 ;
        RECT 74.850 175.255 75.020 177.220 ;
        RECT 75.580 175.255 75.750 177.220 ;
        RECT 94.045 176.950 94.275 177.345 ;
        RECT 101.550 177.125 101.810 177.360 ;
        RECT 107.520 176.950 107.750 196.605 ;
        RECT 108.645 178.350 108.875 197.265 ;
        RECT 109.620 196.905 109.910 197.540 ;
        RECT 109.620 196.485 113.715 196.905 ;
        RECT 110.475 179.385 110.705 194.710 ;
        RECT 110.905 179.385 111.135 194.710 ;
        RECT 111.335 179.385 111.565 194.710 ;
        RECT 111.765 179.385 111.995 194.710 ;
        RECT 112.195 179.385 112.425 194.710 ;
        RECT 112.625 179.385 112.855 194.710 ;
        RECT 113.055 179.385 113.285 194.710 ;
        RECT 113.485 179.385 113.715 194.710 ;
        RECT 113.915 179.385 114.145 194.710 ;
        RECT 114.345 179.385 114.575 194.710 ;
        RECT 114.775 179.385 115.005 194.710 ;
        RECT 118.830 179.620 119.090 200.335 ;
        RECT 123.380 182.905 137.140 183.185 ;
        RECT 123.380 180.155 123.610 182.905 ;
        RECT 131.370 181.560 133.940 181.850 ;
        RECT 128.200 180.975 135.765 181.270 ;
        RECT 128.200 180.080 128.430 180.975 ;
        RECT 118.830 179.330 135.875 179.620 ;
        RECT 136.910 179.355 137.140 182.905 ;
        RECT 144.165 182.030 144.395 183.015 ;
        RECT 137.925 180.995 140.675 181.230 ;
        RECT 140.125 180.910 140.675 180.995 ;
        RECT 140.125 179.820 140.415 180.910 ;
        RECT 145.345 180.805 145.575 184.305 ;
        RECT 148.270 180.910 152.775 181.230 ;
        RECT 151.875 180.495 152.775 180.910 ;
        RECT 135.545 178.735 135.875 179.330 ;
        RECT 135.545 178.435 139.090 178.735 ;
        RECT 94.045 176.695 107.750 176.950 ;
        RECT 103.010 176.110 103.270 176.695 ;
        RECT 116.045 176.020 116.275 176.660 ;
        RECT 109.780 175.505 110.730 175.795 ;
        RECT 116.045 175.735 116.385 176.020 ;
        RECT 117.505 175.975 121.660 176.290 ;
        RECT 59.490 174.965 59.720 175.255 ;
        RECT 60.220 174.965 60.450 175.255 ;
        RECT 60.950 174.965 61.180 175.255 ;
        RECT 61.680 174.965 61.910 175.255 ;
        RECT 62.410 174.965 62.640 175.255 ;
        RECT 63.140 174.965 63.370 175.255 ;
        RECT 63.870 174.965 64.100 175.255 ;
        RECT 64.600 174.965 64.830 175.255 ;
        RECT 65.330 174.965 65.560 175.255 ;
        RECT 66.060 174.965 66.290 175.255 ;
        RECT 66.790 174.965 67.020 175.255 ;
        RECT 67.520 174.965 67.750 175.255 ;
        RECT 68.250 174.965 68.480 175.255 ;
        RECT 68.980 174.965 69.210 175.255 ;
        RECT 69.710 174.965 69.940 175.255 ;
        RECT 70.440 174.965 70.670 175.255 ;
        RECT 71.170 174.965 71.400 175.255 ;
        RECT 71.900 174.965 72.130 175.255 ;
        RECT 72.630 174.965 72.860 175.255 ;
        RECT 73.360 174.965 73.590 175.255 ;
        RECT 74.090 174.965 74.320 175.255 ;
        RECT 74.820 174.965 75.050 175.255 ;
        RECT 75.550 174.965 75.780 175.255 ;
        RECT 59.520 172.630 59.690 174.965 ;
        RECT 60.250 172.630 60.420 174.965 ;
        RECT 60.980 172.630 61.150 174.965 ;
        RECT 61.710 172.630 61.880 174.965 ;
        RECT 62.440 172.630 62.610 174.965 ;
        RECT 63.170 172.630 63.340 174.965 ;
        RECT 63.900 172.630 64.070 174.965 ;
        RECT 64.630 172.630 64.800 174.965 ;
        RECT 65.360 172.630 65.530 174.965 ;
        RECT 66.090 172.630 66.260 174.965 ;
        RECT 66.820 172.630 66.990 174.965 ;
        RECT 67.550 172.630 67.720 174.965 ;
        RECT 68.280 172.630 68.450 174.965 ;
        RECT 69.010 172.630 69.180 174.965 ;
        RECT 69.740 172.630 69.910 174.965 ;
        RECT 70.470 172.630 70.640 174.965 ;
        RECT 71.200 172.630 71.370 174.965 ;
        RECT 71.930 172.630 72.100 174.965 ;
        RECT 72.660 172.630 72.830 174.965 ;
        RECT 73.390 172.630 73.560 174.965 ;
        RECT 74.120 172.630 74.290 174.965 ;
        RECT 74.850 172.630 75.020 174.965 ;
        RECT 75.580 172.630 75.750 174.965 ;
        RECT 89.605 174.495 101.810 174.815 ;
        RECT 59.490 172.340 59.720 172.630 ;
        RECT 60.220 172.340 60.450 172.630 ;
        RECT 60.950 172.340 61.180 172.630 ;
        RECT 61.680 172.340 61.910 172.630 ;
        RECT 62.410 172.340 62.640 172.630 ;
        RECT 63.140 172.340 63.370 172.630 ;
        RECT 63.870 172.340 64.100 172.630 ;
        RECT 64.600 172.340 64.830 172.630 ;
        RECT 65.330 172.340 65.560 172.630 ;
        RECT 66.060 172.340 66.290 172.630 ;
        RECT 66.790 172.340 67.020 172.630 ;
        RECT 67.520 172.340 67.750 172.630 ;
        RECT 68.250 172.340 68.480 172.630 ;
        RECT 68.980 172.340 69.210 172.630 ;
        RECT 69.710 172.340 69.940 172.630 ;
        RECT 70.440 172.340 70.670 172.630 ;
        RECT 71.170 172.340 71.400 172.630 ;
        RECT 71.900 172.340 72.130 172.630 ;
        RECT 72.630 172.340 72.860 172.630 ;
        RECT 73.360 172.340 73.590 172.630 ;
        RECT 74.090 172.340 74.320 172.630 ;
        RECT 74.820 172.340 75.050 172.630 ;
        RECT 75.550 172.340 75.780 172.630 ;
        RECT 59.520 170.155 59.690 172.340 ;
        RECT 60.250 170.155 60.420 172.340 ;
        RECT 60.980 170.155 61.150 172.340 ;
        RECT 61.710 170.155 61.880 172.340 ;
        RECT 62.440 170.155 62.610 172.340 ;
        RECT 63.170 170.155 63.340 172.340 ;
        RECT 63.900 170.155 64.070 172.340 ;
        RECT 64.630 170.155 64.800 172.340 ;
        RECT 65.360 170.155 65.530 172.340 ;
        RECT 66.090 170.155 66.260 172.340 ;
        RECT 66.820 170.155 66.990 172.340 ;
        RECT 67.550 170.155 67.720 172.340 ;
        RECT 68.280 170.155 68.450 172.340 ;
        RECT 69.010 170.155 69.180 172.340 ;
        RECT 69.740 170.155 69.910 172.340 ;
        RECT 70.470 170.155 70.640 172.340 ;
        RECT 71.200 170.155 71.370 172.340 ;
        RECT 71.930 170.155 72.100 172.340 ;
        RECT 72.660 170.155 72.830 172.340 ;
        RECT 73.390 170.155 73.560 172.340 ;
        RECT 74.120 170.155 74.290 172.340 ;
        RECT 74.850 170.155 75.020 172.340 ;
        RECT 75.580 170.155 75.750 172.340 ;
        RECT 94.190 171.695 107.950 171.975 ;
        RECT 59.490 169.865 59.720 170.155 ;
        RECT 60.220 169.865 60.450 170.155 ;
        RECT 60.950 169.865 61.180 170.155 ;
        RECT 61.680 169.865 61.910 170.155 ;
        RECT 62.410 169.865 62.640 170.155 ;
        RECT 63.140 169.865 63.370 170.155 ;
        RECT 63.870 169.865 64.100 170.155 ;
        RECT 64.600 169.865 64.830 170.155 ;
        RECT 65.330 169.865 65.560 170.155 ;
        RECT 66.060 169.865 66.290 170.155 ;
        RECT 66.790 169.865 67.020 170.155 ;
        RECT 67.520 169.865 67.750 170.155 ;
        RECT 68.250 169.865 68.480 170.155 ;
        RECT 68.980 169.865 69.210 170.155 ;
        RECT 69.710 169.865 69.940 170.155 ;
        RECT 70.440 169.865 70.670 170.155 ;
        RECT 71.170 169.865 71.400 170.155 ;
        RECT 71.900 169.865 72.130 170.155 ;
        RECT 72.630 169.865 72.860 170.155 ;
        RECT 73.360 169.865 73.590 170.155 ;
        RECT 74.090 169.865 74.320 170.155 ;
        RECT 74.820 169.865 75.050 170.155 ;
        RECT 75.550 169.865 75.780 170.155 ;
        RECT 59.520 167.730 59.690 169.865 ;
        RECT 60.250 167.730 60.420 169.865 ;
        RECT 60.980 167.730 61.150 169.865 ;
        RECT 61.710 167.730 61.880 169.865 ;
        RECT 62.440 167.730 62.610 169.865 ;
        RECT 63.170 167.730 63.340 169.865 ;
        RECT 63.900 167.730 64.070 169.865 ;
        RECT 64.630 167.730 64.800 169.865 ;
        RECT 65.360 167.730 65.530 169.865 ;
        RECT 66.090 167.730 66.260 169.865 ;
        RECT 66.820 167.730 66.990 169.865 ;
        RECT 67.550 167.730 67.720 169.865 ;
        RECT 68.280 167.730 68.450 169.865 ;
        RECT 69.010 167.730 69.180 169.865 ;
        RECT 69.740 167.730 69.910 169.865 ;
        RECT 70.470 167.730 70.640 169.865 ;
        RECT 71.200 167.730 71.370 169.865 ;
        RECT 71.930 167.730 72.100 169.865 ;
        RECT 72.660 167.730 72.830 169.865 ;
        RECT 73.390 167.730 73.560 169.865 ;
        RECT 74.120 167.730 74.290 169.865 ;
        RECT 74.850 167.730 75.020 169.865 ;
        RECT 75.580 167.730 75.750 169.865 ;
        RECT 94.190 168.945 94.420 171.695 ;
        RECT 102.180 170.350 104.750 170.640 ;
        RECT 99.010 169.765 106.575 170.060 ;
        RECT 99.010 168.870 99.240 169.765 ;
        RECT 89.605 168.120 106.685 168.410 ;
        RECT 107.720 168.145 107.950 171.695 ;
        RECT 114.835 170.820 115.205 175.345 ;
        RECT 108.735 169.785 111.485 170.020 ;
        RECT 110.935 169.700 111.485 169.785 ;
        RECT 110.935 168.610 111.225 169.700 ;
        RECT 116.155 169.595 116.385 175.735 ;
        RECT 89.605 168.090 89.865 168.120 ;
        RECT 59.490 167.440 59.720 167.730 ;
        RECT 60.220 167.440 60.450 167.730 ;
        RECT 60.950 167.440 61.180 167.730 ;
        RECT 61.680 167.440 61.910 167.730 ;
        RECT 62.410 167.440 62.640 167.730 ;
        RECT 63.140 167.440 63.370 167.730 ;
        RECT 63.870 167.440 64.100 167.730 ;
        RECT 64.600 167.440 64.830 167.730 ;
        RECT 65.330 167.440 65.560 167.730 ;
        RECT 66.060 167.440 66.290 167.730 ;
        RECT 66.790 167.440 67.020 167.730 ;
        RECT 67.520 167.440 67.750 167.730 ;
        RECT 68.250 167.440 68.480 167.730 ;
        RECT 68.980 167.440 69.210 167.730 ;
        RECT 69.710 167.440 69.940 167.730 ;
        RECT 70.440 167.440 70.670 167.730 ;
        RECT 71.170 167.440 71.400 167.730 ;
        RECT 71.900 167.440 72.130 167.730 ;
        RECT 72.630 167.440 72.860 167.730 ;
        RECT 73.360 167.440 73.590 167.730 ;
        RECT 74.090 167.440 74.320 167.730 ;
        RECT 74.820 167.440 75.050 167.730 ;
        RECT 75.550 167.440 75.780 167.730 ;
        RECT 106.355 167.525 106.685 168.120 ;
        RECT 59.520 165.315 59.690 167.440 ;
        RECT 60.250 165.315 60.420 167.440 ;
        RECT 60.980 165.315 61.150 167.440 ;
        RECT 61.710 165.315 61.880 167.440 ;
        RECT 62.440 165.315 62.610 167.440 ;
        RECT 63.170 165.315 63.340 167.440 ;
        RECT 63.900 165.315 64.070 167.440 ;
        RECT 64.630 165.315 64.800 167.440 ;
        RECT 65.360 165.315 65.530 167.440 ;
        RECT 66.090 165.315 66.260 167.440 ;
        RECT 66.820 165.315 66.990 167.440 ;
        RECT 67.550 165.315 67.720 167.440 ;
        RECT 68.280 165.315 68.450 167.440 ;
        RECT 69.010 165.315 69.180 167.440 ;
        RECT 69.740 165.315 69.910 167.440 ;
        RECT 70.470 165.315 70.640 167.440 ;
        RECT 71.200 165.315 71.370 167.440 ;
        RECT 71.930 165.315 72.100 167.440 ;
        RECT 72.660 165.315 72.830 167.440 ;
        RECT 73.390 165.315 73.560 167.440 ;
        RECT 74.120 165.315 74.290 167.440 ;
        RECT 74.850 165.315 75.020 167.440 ;
        RECT 75.580 165.315 75.750 167.440 ;
        RECT 106.355 167.225 109.900 167.525 ;
        RECT 59.490 165.025 59.720 165.315 ;
        RECT 60.220 165.025 60.450 165.315 ;
        RECT 60.950 165.025 61.180 165.315 ;
        RECT 61.680 165.025 61.910 165.315 ;
        RECT 62.410 165.025 62.640 165.315 ;
        RECT 63.140 165.025 63.370 165.315 ;
        RECT 63.870 165.025 64.100 165.315 ;
        RECT 64.600 165.025 64.830 165.315 ;
        RECT 65.330 165.025 65.560 165.315 ;
        RECT 66.060 165.025 66.290 165.315 ;
        RECT 66.790 165.025 67.020 165.315 ;
        RECT 67.520 165.025 67.750 165.315 ;
        RECT 68.250 165.025 68.480 165.315 ;
        RECT 68.980 165.025 69.210 165.315 ;
        RECT 69.710 165.025 69.940 165.315 ;
        RECT 70.440 165.025 70.670 165.315 ;
        RECT 71.170 165.025 71.400 165.315 ;
        RECT 71.900 165.025 72.130 165.315 ;
        RECT 72.630 165.025 72.860 165.315 ;
        RECT 73.360 165.025 73.590 165.315 ;
        RECT 74.090 165.025 74.320 165.315 ;
        RECT 74.820 165.025 75.050 165.315 ;
        RECT 75.550 165.025 75.780 165.315 ;
        RECT 59.520 163.100 59.690 165.025 ;
        RECT 60.250 163.100 60.420 165.025 ;
        RECT 60.980 163.100 61.150 165.025 ;
        RECT 61.710 163.100 61.880 165.025 ;
        RECT 62.440 163.100 62.610 165.025 ;
        RECT 63.170 163.100 63.340 165.025 ;
        RECT 63.900 163.100 64.070 165.025 ;
        RECT 64.630 163.100 64.800 165.025 ;
        RECT 65.360 163.100 65.530 165.025 ;
        RECT 66.090 163.100 66.260 165.025 ;
        RECT 66.820 163.100 66.990 165.025 ;
        RECT 67.550 163.100 67.720 165.025 ;
        RECT 68.280 163.100 68.450 165.025 ;
        RECT 69.010 163.100 69.180 165.025 ;
        RECT 69.740 163.100 69.910 165.025 ;
        RECT 70.470 163.100 70.640 165.025 ;
        RECT 71.200 163.100 71.370 165.025 ;
        RECT 71.930 163.100 72.100 165.025 ;
        RECT 72.660 163.100 72.830 165.025 ;
        RECT 73.390 163.100 73.560 165.025 ;
        RECT 74.120 163.100 74.290 165.025 ;
        RECT 74.850 163.100 75.020 165.025 ;
        RECT 75.580 163.100 75.750 165.025 ;
        RECT 59.490 162.810 59.720 163.100 ;
        RECT 60.220 162.810 60.450 163.100 ;
        RECT 60.950 162.810 61.180 163.100 ;
        RECT 61.680 162.810 61.910 163.100 ;
        RECT 62.410 162.810 62.640 163.100 ;
        RECT 63.140 162.810 63.370 163.100 ;
        RECT 63.870 162.810 64.100 163.100 ;
        RECT 64.600 162.810 64.830 163.100 ;
        RECT 65.330 162.810 65.560 163.100 ;
        RECT 66.060 162.810 66.290 163.100 ;
        RECT 66.790 162.810 67.020 163.100 ;
        RECT 67.520 162.810 67.750 163.100 ;
        RECT 68.250 162.810 68.480 163.100 ;
        RECT 68.980 162.810 69.210 163.100 ;
        RECT 69.710 162.810 69.940 163.100 ;
        RECT 70.440 162.810 70.670 163.100 ;
        RECT 71.170 162.810 71.400 163.100 ;
        RECT 71.900 162.810 72.130 163.100 ;
        RECT 72.630 162.810 72.860 163.100 ;
        RECT 73.360 162.810 73.590 163.100 ;
        RECT 74.090 162.810 74.320 163.100 ;
        RECT 74.820 162.810 75.050 163.100 ;
        RECT 75.550 162.810 75.780 163.100 ;
        RECT 59.520 160.580 59.690 162.810 ;
        RECT 60.250 160.580 60.420 162.810 ;
        RECT 60.980 160.580 61.150 162.810 ;
        RECT 61.710 160.580 61.880 162.810 ;
        RECT 62.440 160.580 62.610 162.810 ;
        RECT 63.170 160.580 63.340 162.810 ;
        RECT 63.900 160.580 64.070 162.810 ;
        RECT 64.630 160.580 64.800 162.810 ;
        RECT 65.360 160.580 65.530 162.810 ;
        RECT 66.090 160.580 66.260 162.810 ;
        RECT 66.820 160.580 66.990 162.810 ;
        RECT 67.550 160.580 67.720 162.810 ;
        RECT 68.280 160.580 68.450 162.810 ;
        RECT 69.010 160.580 69.180 162.810 ;
        RECT 69.740 160.580 69.910 162.810 ;
        RECT 70.470 160.580 70.640 162.810 ;
        RECT 71.200 160.580 71.370 162.810 ;
        RECT 71.930 160.580 72.100 162.810 ;
        RECT 72.660 160.580 72.830 162.810 ;
        RECT 73.390 160.580 73.560 162.810 ;
        RECT 74.120 160.580 74.290 162.810 ;
        RECT 74.850 160.580 75.020 162.810 ;
        RECT 75.580 160.580 75.750 162.810 ;
        RECT 59.490 160.290 59.720 160.580 ;
        RECT 60.220 160.290 60.450 160.580 ;
        RECT 60.950 160.290 61.180 160.580 ;
        RECT 61.680 160.290 61.910 160.580 ;
        RECT 62.410 160.290 62.640 160.580 ;
        RECT 63.140 160.290 63.370 160.580 ;
        RECT 63.870 160.290 64.100 160.580 ;
        RECT 64.600 160.290 64.830 160.580 ;
        RECT 65.330 160.290 65.560 160.580 ;
        RECT 66.060 160.290 66.290 160.580 ;
        RECT 66.790 160.290 67.020 160.580 ;
        RECT 67.520 160.290 67.750 160.580 ;
        RECT 68.250 160.290 68.480 160.580 ;
        RECT 68.980 160.290 69.210 160.580 ;
        RECT 69.710 160.290 69.940 160.580 ;
        RECT 70.440 160.290 70.670 160.580 ;
        RECT 71.170 160.290 71.400 160.580 ;
        RECT 71.900 160.290 72.130 160.580 ;
        RECT 72.630 160.290 72.860 160.580 ;
        RECT 73.360 160.290 73.590 160.580 ;
        RECT 74.090 160.290 74.320 160.580 ;
        RECT 74.820 160.290 75.050 160.580 ;
        RECT 75.550 160.290 75.780 160.580 ;
        RECT 59.520 158.045 59.690 160.290 ;
        RECT 60.250 158.045 60.420 160.290 ;
        RECT 60.980 158.045 61.150 160.290 ;
        RECT 61.710 158.045 61.880 160.290 ;
        RECT 62.440 158.045 62.610 160.290 ;
        RECT 63.170 158.045 63.340 160.290 ;
        RECT 63.900 158.045 64.070 160.290 ;
        RECT 64.630 158.045 64.800 160.290 ;
        RECT 65.360 158.045 65.530 160.290 ;
        RECT 66.090 158.045 66.260 160.290 ;
        RECT 66.820 158.045 66.990 160.290 ;
        RECT 67.550 158.045 67.720 160.290 ;
        RECT 68.280 158.045 68.450 160.290 ;
        RECT 69.010 158.045 69.180 160.290 ;
        RECT 69.740 158.045 69.910 160.290 ;
        RECT 70.470 158.045 70.640 160.290 ;
        RECT 71.200 158.045 71.370 160.290 ;
        RECT 71.930 158.045 72.100 160.290 ;
        RECT 72.660 158.045 72.830 160.290 ;
        RECT 73.390 158.045 73.560 160.290 ;
        RECT 74.120 158.045 74.290 160.290 ;
        RECT 74.850 158.045 75.020 160.290 ;
        RECT 75.580 158.045 75.750 160.290 ;
        RECT 59.490 157.755 59.720 158.045 ;
        RECT 60.220 157.755 60.450 158.045 ;
        RECT 60.950 157.755 61.180 158.045 ;
        RECT 61.680 157.755 61.910 158.045 ;
        RECT 62.410 157.755 62.640 158.045 ;
        RECT 63.140 157.755 63.370 158.045 ;
        RECT 63.870 157.755 64.100 158.045 ;
        RECT 64.600 157.755 64.830 158.045 ;
        RECT 65.330 157.755 65.560 158.045 ;
        RECT 66.060 157.755 66.290 158.045 ;
        RECT 66.790 157.755 67.020 158.045 ;
        RECT 67.520 157.755 67.750 158.045 ;
        RECT 68.250 157.755 68.480 158.045 ;
        RECT 68.980 157.755 69.210 158.045 ;
        RECT 69.710 157.755 69.940 158.045 ;
        RECT 70.440 157.755 70.670 158.045 ;
        RECT 71.170 157.755 71.400 158.045 ;
        RECT 71.900 157.755 72.130 158.045 ;
        RECT 72.630 157.755 72.860 158.045 ;
        RECT 73.360 157.755 73.590 158.045 ;
        RECT 74.090 157.755 74.320 158.045 ;
        RECT 74.820 157.755 75.050 158.045 ;
        RECT 75.550 157.755 75.780 158.045 ;
        RECT 59.520 155.670 59.690 157.755 ;
        RECT 60.250 155.670 60.420 157.755 ;
        RECT 60.980 155.670 61.150 157.755 ;
        RECT 61.710 155.670 61.880 157.755 ;
        RECT 62.440 155.670 62.610 157.755 ;
        RECT 63.170 155.670 63.340 157.755 ;
        RECT 63.900 155.670 64.070 157.755 ;
        RECT 64.630 155.670 64.800 157.755 ;
        RECT 65.360 155.670 65.530 157.755 ;
        RECT 66.090 155.670 66.260 157.755 ;
        RECT 66.820 155.670 66.990 157.755 ;
        RECT 67.550 155.670 67.720 157.755 ;
        RECT 68.280 155.670 68.450 157.755 ;
        RECT 69.010 155.670 69.180 157.755 ;
        RECT 69.740 155.670 69.910 157.755 ;
        RECT 70.470 155.670 70.640 157.755 ;
        RECT 71.200 155.670 71.370 157.755 ;
        RECT 71.930 155.670 72.100 157.755 ;
        RECT 72.660 155.670 72.830 157.755 ;
        RECT 73.390 155.670 73.560 157.755 ;
        RECT 74.120 155.670 74.290 157.755 ;
        RECT 74.850 155.670 75.020 157.755 ;
        RECT 75.580 155.670 75.750 157.755 ;
        RECT 59.490 155.380 59.720 155.670 ;
        RECT 60.220 155.380 60.450 155.670 ;
        RECT 60.950 155.380 61.180 155.670 ;
        RECT 61.680 155.380 61.910 155.670 ;
        RECT 62.410 155.380 62.640 155.670 ;
        RECT 63.140 155.380 63.370 155.670 ;
        RECT 63.870 155.380 64.100 155.670 ;
        RECT 64.600 155.380 64.830 155.670 ;
        RECT 65.330 155.380 65.560 155.670 ;
        RECT 66.060 155.380 66.290 155.670 ;
        RECT 66.790 155.380 67.020 155.670 ;
        RECT 67.520 155.380 67.750 155.670 ;
        RECT 68.250 155.380 68.480 155.670 ;
        RECT 68.980 155.380 69.210 155.670 ;
        RECT 69.710 155.380 69.940 155.670 ;
        RECT 70.440 155.380 70.670 155.670 ;
        RECT 71.170 155.380 71.400 155.670 ;
        RECT 71.900 155.380 72.130 155.670 ;
        RECT 72.630 155.380 72.860 155.670 ;
        RECT 73.360 155.380 73.590 155.670 ;
        RECT 74.090 155.380 74.320 155.670 ;
        RECT 74.820 155.380 75.050 155.670 ;
        RECT 75.550 155.380 75.780 155.670 ;
        RECT 46.750 154.480 56.785 154.770 ;
        RECT 18.990 122.780 19.280 153.675 ;
        RECT 59.520 153.150 59.690 155.380 ;
        RECT 60.250 153.150 60.420 155.380 ;
        RECT 60.980 153.150 61.150 155.380 ;
        RECT 61.710 153.150 61.880 155.380 ;
        RECT 62.440 153.150 62.610 155.380 ;
        RECT 63.170 153.150 63.340 155.380 ;
        RECT 63.900 153.150 64.070 155.380 ;
        RECT 64.630 153.150 64.800 155.380 ;
        RECT 65.360 153.150 65.530 155.380 ;
        RECT 66.090 153.150 66.260 155.380 ;
        RECT 66.820 153.150 66.990 155.380 ;
        RECT 67.550 153.150 67.720 155.380 ;
        RECT 68.280 153.150 68.450 155.380 ;
        RECT 69.010 153.150 69.180 155.380 ;
        RECT 69.740 153.150 69.910 155.380 ;
        RECT 70.470 153.150 70.640 155.380 ;
        RECT 71.200 153.150 71.370 155.380 ;
        RECT 71.930 153.150 72.100 155.380 ;
        RECT 72.660 153.150 72.830 155.380 ;
        RECT 73.390 153.150 73.560 155.380 ;
        RECT 74.120 153.150 74.290 155.380 ;
        RECT 74.850 153.150 75.020 155.380 ;
        RECT 75.580 153.150 75.750 155.380 ;
        RECT 59.490 152.860 59.720 153.150 ;
        RECT 60.220 152.860 60.450 153.150 ;
        RECT 60.950 152.860 61.180 153.150 ;
        RECT 61.680 152.860 61.910 153.150 ;
        RECT 62.410 152.860 62.640 153.150 ;
        RECT 63.140 152.860 63.370 153.150 ;
        RECT 63.870 152.860 64.100 153.150 ;
        RECT 64.600 152.860 64.830 153.150 ;
        RECT 65.330 152.860 65.560 153.150 ;
        RECT 66.060 152.860 66.290 153.150 ;
        RECT 66.790 152.860 67.020 153.150 ;
        RECT 67.520 152.860 67.750 153.150 ;
        RECT 68.250 152.860 68.480 153.150 ;
        RECT 68.980 152.860 69.210 153.150 ;
        RECT 69.710 152.860 69.940 153.150 ;
        RECT 70.440 152.860 70.670 153.150 ;
        RECT 71.170 152.860 71.400 153.150 ;
        RECT 71.900 152.860 72.130 153.150 ;
        RECT 72.630 152.860 72.860 153.150 ;
        RECT 73.360 152.860 73.590 153.150 ;
        RECT 74.090 152.860 74.320 153.150 ;
        RECT 74.820 152.860 75.050 153.150 ;
        RECT 75.550 152.860 75.780 153.150 ;
        RECT 59.520 151.455 59.690 152.860 ;
        RECT 60.250 151.455 60.420 152.860 ;
        RECT 60.980 151.455 61.150 152.860 ;
        RECT 61.710 151.455 61.880 152.860 ;
        RECT 62.440 151.455 62.610 152.860 ;
        RECT 63.170 151.455 63.340 152.860 ;
        RECT 63.900 151.455 64.070 152.860 ;
        RECT 64.630 151.455 64.800 152.860 ;
        RECT 65.360 151.455 65.530 152.860 ;
        RECT 66.090 151.455 66.260 152.860 ;
        RECT 66.820 151.455 66.990 152.860 ;
        RECT 67.550 151.455 67.720 152.860 ;
        RECT 68.280 151.455 68.450 152.860 ;
        RECT 69.010 151.455 69.180 152.860 ;
        RECT 69.740 151.455 69.910 152.860 ;
        RECT 70.470 151.455 70.640 152.860 ;
        RECT 71.200 151.455 71.370 152.860 ;
        RECT 71.930 151.455 72.100 152.860 ;
        RECT 72.660 151.455 72.830 152.860 ;
        RECT 73.390 151.455 73.560 152.860 ;
        RECT 74.120 151.455 74.290 152.860 ;
        RECT 74.850 151.455 75.020 152.860 ;
        RECT 75.580 151.455 75.750 152.860 ;
        RECT 77.405 150.010 85.960 150.960 ;
        RECT 38.300 145.070 60.015 146.020 ;
        RECT 38.300 129.505 39.375 145.070 ;
        RECT 42.850 142.545 60.015 143.495 ;
        RECT 42.850 142.215 43.925 142.545 ;
        RECT 61.125 136.660 62.070 149.825 ;
        RECT 62.875 149.790 63.775 149.800 ;
        RECT 62.865 149.265 63.825 149.790 ;
        RECT 62.865 148.890 64.200 149.265 ;
        RECT 62.865 143.500 63.825 148.890 ;
        RECT 70.140 146.020 71.160 149.565 ;
        RECT 78.445 147.585 78.675 147.950 ;
        RECT 78.445 146.920 81.405 147.585 ;
        RECT 69.800 145.070 71.160 146.020 ;
        RECT 70.140 144.490 71.160 145.070 ;
        RECT 70.140 144.170 71.565 144.490 ;
        RECT 62.865 142.550 64.290 143.500 ;
        RECT 62.865 136.975 63.825 142.550 ;
        RECT 70.140 142.295 71.160 144.170 ;
        RECT 70.140 141.335 71.435 142.295 ;
        RECT 49.915 136.120 56.010 136.490 ;
        RECT 49.915 133.515 50.830 136.120 ;
        RECT 57.605 136.055 65.595 136.660 ;
        RECT 57.605 135.370 58.555 136.055 ;
        RECT 61.125 135.680 62.070 136.055 ;
        RECT 61.125 135.390 62.075 135.680 ;
        RECT 61.125 135.335 62.070 135.390 ;
        RECT 64.640 135.370 65.595 136.055 ;
        RECT 70.140 135.610 71.160 141.335 ;
        RECT 80.900 139.960 81.405 146.920 ;
        RECT 79.900 139.300 81.405 139.960 ;
        RECT 79.900 138.950 80.130 139.300 ;
        RECT 80.900 138.550 81.405 139.300 ;
        RECT 80.900 137.915 82.215 138.550 ;
        RECT 81.985 137.540 82.215 137.915 ;
        RECT 85.010 137.590 85.960 150.010 ;
        RECT 94.035 147.260 94.265 167.165 ;
        RECT 95.570 149.035 95.800 166.435 ;
        RECT 96.000 149.035 96.230 166.435 ;
        RECT 96.430 149.035 96.660 166.435 ;
        RECT 96.860 149.035 97.090 166.435 ;
        RECT 97.290 149.035 97.520 166.435 ;
        RECT 97.720 149.035 97.950 166.435 ;
        RECT 98.150 149.035 98.380 166.435 ;
        RECT 98.580 149.035 98.810 166.435 ;
        RECT 99.010 149.035 99.240 166.435 ;
        RECT 99.440 149.035 99.670 166.435 ;
        RECT 99.870 149.035 100.100 166.435 ;
        RECT 94.035 147.030 95.360 147.260 ;
        RECT 101.205 147.045 107.120 147.275 ;
        RECT 94.035 146.635 94.265 147.030 ;
        RECT 101.550 146.805 101.810 147.045 ;
        RECT 107.510 146.635 107.740 166.290 ;
        RECT 108.635 148.035 108.865 166.950 ;
        RECT 109.610 166.590 109.900 167.225 ;
        RECT 109.610 166.170 113.705 166.590 ;
        RECT 110.465 149.070 110.695 164.395 ;
        RECT 110.895 149.070 111.125 164.395 ;
        RECT 111.325 149.070 111.555 164.395 ;
        RECT 111.755 149.070 111.985 164.395 ;
        RECT 112.185 149.070 112.415 164.395 ;
        RECT 112.615 149.070 112.845 164.395 ;
        RECT 113.045 149.070 113.275 164.395 ;
        RECT 113.475 149.070 113.705 164.395 ;
        RECT 113.905 149.070 114.135 164.395 ;
        RECT 114.335 149.070 114.565 164.395 ;
        RECT 114.765 149.070 114.995 164.395 ;
        RECT 118.830 155.710 119.090 170.020 ;
        RECT 123.225 158.470 123.455 178.375 ;
        RECT 124.760 160.245 124.990 177.645 ;
        RECT 125.190 160.245 125.420 177.645 ;
        RECT 125.620 160.245 125.850 177.645 ;
        RECT 126.050 160.245 126.280 177.645 ;
        RECT 126.480 160.245 126.710 177.645 ;
        RECT 126.910 160.245 127.140 177.645 ;
        RECT 127.340 160.245 127.570 177.645 ;
        RECT 127.770 160.245 128.000 177.645 ;
        RECT 128.200 160.245 128.430 177.645 ;
        RECT 128.630 160.245 128.860 177.645 ;
        RECT 129.060 160.245 129.290 177.645 ;
        RECT 123.225 158.240 124.550 158.470 ;
        RECT 130.395 158.255 136.310 158.485 ;
        RECT 123.225 157.845 123.455 158.240 ;
        RECT 130.770 158.020 131.030 158.255 ;
        RECT 136.700 157.845 136.930 177.500 ;
        RECT 137.825 159.245 138.055 178.160 ;
        RECT 138.800 177.800 139.090 178.435 ;
        RECT 138.800 177.380 142.895 177.800 ;
        RECT 139.655 160.280 139.885 175.605 ;
        RECT 140.085 160.280 140.315 175.605 ;
        RECT 140.515 160.280 140.745 175.605 ;
        RECT 140.945 160.280 141.175 175.605 ;
        RECT 141.375 160.280 141.605 175.605 ;
        RECT 141.805 160.280 142.035 175.605 ;
        RECT 142.235 160.280 142.465 175.605 ;
        RECT 142.665 160.280 142.895 175.605 ;
        RECT 143.095 160.280 143.325 175.605 ;
        RECT 143.525 160.280 143.755 175.605 ;
        RECT 143.955 160.280 144.185 175.605 ;
        RECT 123.225 157.590 136.930 157.845 ;
        RECT 118.830 155.390 131.030 155.710 ;
        RECT 131.950 154.565 132.315 157.590 ;
        RECT 138.085 153.465 138.315 157.485 ;
        RECT 119.205 153.010 138.315 153.465 ;
        RECT 94.035 146.380 107.740 146.635 ;
        RECT 90.640 144.175 101.810 144.495 ;
        RECT 90.640 144.170 90.900 144.175 ;
        RECT 103.010 141.455 103.270 146.380 ;
        RECT 116.035 145.835 116.265 146.305 ;
        RECT 119.205 145.835 119.515 153.010 ;
        RECT 116.035 145.555 119.515 145.835 ;
        RECT 103.010 141.060 105.830 141.455 ;
        RECT 107.065 138.810 108.015 144.845 ;
        RECT 131.950 143.375 132.320 152.310 ;
        RECT 138.320 143.375 138.600 143.905 ;
        RECT 131.950 142.935 145.920 143.375 ;
        RECT 138.510 142.175 138.740 142.935 ;
        RECT 135.545 141.425 135.870 141.750 ;
        RECT 108.840 141.095 146.075 141.425 ;
        RECT 135.900 135.060 136.130 141.095 ;
        RECT 138.510 135.060 138.740 140.200 ;
        RECT 115.990 134.585 133.940 134.915 ;
        RECT 57.085 118.945 57.315 133.205 ;
        RECT 57.965 118.945 58.195 133.205 ;
        RECT 58.845 116.775 59.075 133.205 ;
        RECT 59.725 118.945 59.955 133.205 ;
        RECT 60.605 116.775 60.835 133.205 ;
        RECT 61.485 118.945 61.715 133.205 ;
        RECT 62.365 116.775 62.595 133.205 ;
        RECT 63.245 118.945 63.475 133.205 ;
        RECT 64.125 116.775 64.355 133.205 ;
        RECT 65.005 118.945 65.235 133.205 ;
        RECT 65.885 118.945 66.115 133.205 ;
        RECT 52.590 116.325 55.660 116.615 ;
        RECT 54.485 115.020 54.940 116.325 ;
        RECT 57.975 116.165 64.355 116.775 ;
        RECT 54.485 114.425 56.255 115.020 ;
        RECT 54.945 113.335 56.255 114.425 ;
        RECT 57.975 114.305 58.205 116.165 ;
        RECT 58.845 116.150 59.075 116.165 ;
        RECT 59.735 114.305 59.965 116.165 ;
        RECT 60.605 116.150 60.835 116.165 ;
        RECT 61.495 114.305 61.725 116.165 ;
        RECT 62.365 116.150 62.595 116.165 ;
        RECT 54.130 106.780 54.360 106.820 ;
        RECT 57.095 106.780 57.325 106.820 ;
        RECT 58.855 106.780 59.085 106.820 ;
        RECT 60.615 106.780 60.845 106.820 ;
        RECT 62.375 106.780 62.605 106.820 ;
        RECT 54.130 106.580 62.605 106.780 ;
        RECT 54.130 106.530 54.360 106.580 ;
        RECT 57.095 106.530 57.325 106.580 ;
        RECT 58.855 106.530 59.085 106.580 ;
        RECT 60.615 106.530 60.845 106.580 ;
        RECT 62.375 106.530 62.605 106.580 ;
        RECT 60.225 103.930 60.595 105.475 ;
        RECT 67.535 103.930 68.030 104.065 ;
        RECT 60.225 103.290 68.030 103.930 ;
        RECT 67.260 103.165 68.030 103.290 ;
        RECT 67.260 90.725 67.535 103.165 ;
        RECT 67.260 90.375 68.510 90.725 ;
        RECT 69.385 89.650 69.615 133.070 ;
        RECT 70.115 91.720 70.345 133.070 ;
        RECT 70.845 89.650 71.075 133.070 ;
        RECT 71.575 91.720 71.805 133.070 ;
        RECT 72.305 89.650 72.535 133.070 ;
        RECT 73.035 91.720 73.265 133.070 ;
        RECT 73.765 89.650 73.995 133.070 ;
        RECT 74.495 91.720 74.725 133.070 ;
        RECT 75.225 89.650 75.455 133.070 ;
        RECT 75.955 91.720 76.185 133.070 ;
        RECT 76.685 89.650 76.915 133.070 ;
        RECT 77.415 91.720 77.645 133.070 ;
        RECT 78.145 89.650 78.375 133.070 ;
        RECT 88.045 129.830 88.275 133.935 ;
        RECT 88.925 129.830 89.155 133.935 ;
        RECT 89.805 129.830 90.035 133.935 ;
        RECT 90.685 129.830 90.915 133.935 ;
        RECT 91.565 129.830 91.795 133.935 ;
        RECT 92.445 129.830 92.675 133.935 ;
        RECT 93.325 129.830 93.555 133.935 ;
        RECT 102.030 133.230 104.830 133.730 ;
        RECT 102.030 132.165 102.830 133.230 ;
        RECT 104.030 132.165 104.830 133.230 ;
        RECT 102.030 131.665 104.830 132.165 ;
        RECT 102.030 129.730 102.830 131.665 ;
        RECT 104.030 130.030 104.830 131.665 ;
        RECT 105.530 133.230 108.330 133.730 ;
        RECT 105.530 130.230 106.330 133.230 ;
        RECT 109.030 133.215 109.830 133.730 ;
        RECT 111.530 133.215 112.330 133.730 ;
        RECT 114.595 133.535 132.310 133.865 ;
        RECT 109.030 132.830 110.380 133.215 ;
        RECT 110.980 132.830 112.330 133.215 ;
        RECT 109.030 132.610 110.530 132.830 ;
        RECT 110.830 132.610 112.330 132.830 ;
        RECT 107.030 131.230 108.330 131.730 ;
        RECT 107.530 130.230 108.330 131.230 ;
        RECT 105.530 130.030 108.330 130.230 ;
        RECT 109.030 130.030 109.830 132.610 ;
        RECT 110.230 132.430 111.130 132.610 ;
        RECT 110.405 132.005 110.955 132.430 ;
        RECT 104.030 129.730 109.830 130.030 ;
        RECT 111.530 130.030 112.330 132.610 ;
        RECT 136.755 132.460 137.025 133.800 ;
        RECT 136.755 132.230 137.045 132.460 ;
        RECT 111.530 129.625 113.935 130.030 ;
        RECT 92.900 127.705 99.645 127.935 ;
        RECT 84.960 124.875 96.745 125.165 ;
        RECT 84.960 104.065 85.270 124.875 ;
        RECT 99.370 123.180 99.645 127.705 ;
        RECT 112.235 125.435 112.495 125.755 ;
        RECT 112.235 125.165 112.490 125.435 ;
        RECT 100.530 124.875 112.490 125.165 ;
        RECT 112.235 124.870 112.490 124.875 ;
        RECT 85.955 109.985 86.185 123.020 ;
        RECT 86.835 109.985 87.065 123.020 ;
        RECT 87.715 109.985 87.945 123.020 ;
        RECT 88.595 109.985 88.825 123.020 ;
        RECT 89.475 109.985 89.705 123.020 ;
        RECT 90.355 109.985 90.585 123.020 ;
        RECT 91.235 109.985 91.465 123.020 ;
        RECT 92.115 109.985 92.345 123.020 ;
        RECT 92.995 109.985 93.225 123.020 ;
        RECT 93.875 109.985 94.105 123.020 ;
        RECT 94.755 109.985 94.985 123.020 ;
        RECT 95.635 109.985 95.865 123.020 ;
        RECT 96.515 109.985 96.745 123.020 ;
        RECT 97.395 109.985 97.625 123.020 ;
        RECT 99.370 122.860 99.905 123.180 ;
        RECT 100.555 109.985 100.785 123.020 ;
        RECT 101.435 109.985 101.665 123.020 ;
        RECT 102.315 109.985 102.545 123.020 ;
        RECT 103.195 109.985 103.425 123.020 ;
        RECT 104.075 109.985 104.305 123.020 ;
        RECT 104.955 109.985 105.185 123.020 ;
        RECT 105.835 109.985 106.065 123.020 ;
        RECT 106.715 109.985 106.945 123.020 ;
        RECT 107.595 109.985 107.825 123.020 ;
        RECT 108.475 109.985 108.705 123.020 ;
        RECT 109.355 109.985 109.585 123.020 ;
        RECT 110.235 109.985 110.465 123.020 ;
        RECT 111.115 109.985 111.345 123.020 ;
        RECT 111.995 109.985 112.225 123.020 ;
        RECT 112.875 109.985 113.105 123.020 ;
        RECT 115.015 116.005 115.965 116.295 ;
        RECT 96.210 108.005 96.440 108.415 ;
        RECT 112.230 108.325 112.490 108.335 ;
        RECT 111.695 108.035 112.490 108.325 ;
        RECT 112.230 108.015 112.490 108.035 ;
        RECT 87.715 107.715 94.985 108.005 ;
        RECT 96.210 107.715 110.465 108.005 ;
        RECT 84.510 103.165 85.370 104.065 ;
        RECT 84.960 81.085 85.270 103.165 ;
        RECT 87.715 101.190 87.945 107.715 ;
        RECT 108.905 101.190 109.165 107.715 ;
        RECT 114.530 106.915 117.710 107.145 ;
        RECT 86.670 100.900 103.025 101.190 ;
        RECT 104.970 100.900 109.165 101.190 ;
        RECT 85.790 83.390 86.020 98.260 ;
        RECT 86.670 83.390 86.900 98.260 ;
        RECT 87.550 83.390 87.780 98.260 ;
        RECT 88.430 83.390 88.660 98.260 ;
        RECT 89.310 83.390 89.540 98.260 ;
        RECT 90.190 83.390 90.420 98.260 ;
        RECT 91.070 83.390 91.300 98.260 ;
        RECT 91.950 83.390 92.180 98.260 ;
        RECT 92.830 83.390 93.060 98.260 ;
        RECT 93.710 83.390 93.940 98.260 ;
        RECT 94.590 83.390 94.820 98.260 ;
        RECT 95.470 83.390 95.700 98.260 ;
        RECT 96.350 83.390 96.580 98.260 ;
        RECT 97.230 83.390 97.460 98.260 ;
        RECT 98.110 83.390 98.340 98.260 ;
        RECT 98.990 83.390 99.220 98.260 ;
        RECT 99.870 83.390 100.100 98.260 ;
        RECT 100.750 83.390 100.980 98.260 ;
        RECT 101.630 83.390 101.860 98.260 ;
        RECT 102.690 81.990 103.025 100.900 ;
        RECT 104.085 94.365 104.315 98.885 ;
        RECT 104.965 94.365 105.195 98.885 ;
        RECT 105.845 94.365 106.075 98.885 ;
        RECT 106.725 94.365 106.955 98.885 ;
        RECT 107.605 94.365 107.835 98.885 ;
        RECT 108.485 94.365 108.715 98.885 ;
        RECT 103.830 92.265 107.835 92.585 ;
        RECT 105.240 88.375 105.465 92.265 ;
        RECT 105.240 88.085 105.470 88.375 ;
        RECT 105.240 83.000 105.465 88.085 ;
        RECT 108.905 87.260 109.165 100.900 ;
        RECT 111.215 91.420 111.475 106.305 ;
        RECT 109.970 91.190 111.475 91.420 ;
        RECT 112.235 87.750 112.495 106.260 ;
        RECT 112.995 103.725 113.225 105.225 ;
        RECT 112.995 103.475 116.140 103.725 ;
        RECT 112.995 102.225 113.225 103.475 ;
        RECT 110.240 87.520 112.495 87.750 ;
        RECT 106.790 86.950 109.165 87.260 ;
        RECT 105.240 82.630 106.615 83.000 ;
        RECT 102.690 81.630 105.710 81.990 ;
        RECT 89.290 81.085 89.560 81.105 ;
        RECT 97.210 81.085 97.480 81.105 ;
        RECT 84.960 80.750 99.010 81.085 ;
        RECT 104.195 80.345 106.300 80.555 ;
        RECT 102.285 80.115 106.300 80.345 ;
        RECT 104.195 79.965 106.300 80.115 ;
        RECT 109.190 79.965 111.295 80.555 ;
        RECT 106.360 75.835 106.650 76.065 ;
        RECT 106.375 65.090 106.620 75.835 ;
      LAYER met2 ;
        RECT 55.840 209.750 75.155 211.745 ;
        RECT 64.400 204.885 67.550 206.880 ;
        RECT 111.235 200.015 119.090 200.335 ;
        RECT 86.975 198.725 87.235 198.730 ;
        RECT 42.845 152.505 43.925 152.875 ;
        RECT 38.300 127.625 39.375 129.825 ;
        RECT 42.850 129.130 43.925 152.505 ;
        RECT 61.125 149.390 62.075 198.705 ;
        RECT 79.220 198.430 87.235 198.725 ;
        RECT 62.865 149.400 63.815 189.540 ;
        RECT 79.220 180.310 79.910 198.430 ;
        RECT 86.975 198.410 87.235 198.430 ;
        RECT 140.415 180.910 148.530 181.230 ;
        RECT 70.140 179.600 79.910 180.310 ;
        RECT 70.140 148.685 71.160 179.600 ;
        RECT 88.175 174.495 89.865 174.815 ;
        RECT 101.550 174.495 101.810 177.445 ;
        RECT 88.175 174.445 88.455 174.495 ;
        RECT 88.175 168.090 89.865 168.410 ;
        RECT 88.175 168.040 88.455 168.090 ;
        RECT 71.305 144.170 90.900 144.490 ;
        RECT 101.550 144.175 101.810 147.125 ;
        RECT 103.010 145.150 103.270 176.430 ;
        RECT 111.225 169.700 119.090 170.020 ;
        RECT 130.770 155.390 131.030 158.340 ;
        RECT 131.950 151.985 132.320 154.885 ;
        RECT 151.875 150.220 152.775 180.815 ;
        RECT 126.950 149.630 152.775 150.220 ;
        RECT 126.950 142.295 127.550 149.630 ;
        RECT 71.175 141.695 127.550 142.295 ;
        RECT 71.175 141.335 71.435 141.695 ;
        RECT 135.545 141.425 135.870 147.450 ;
        RECT 138.320 143.585 138.600 148.480 ;
        RECT 151.805 146.675 152.710 149.630 ;
        RECT 49.555 132.070 51.175 133.940 ;
        RECT 49.800 132.055 50.880 132.070 ;
        RECT 42.850 128.235 49.555 129.130 ;
        RECT 42.850 127.625 43.925 128.235 ;
        RECT 38.295 127.255 39.375 127.625 ;
        RECT 42.845 127.255 43.925 127.625 ;
        RECT 48.495 72.535 49.555 128.235 ;
        RECT 112.235 125.435 112.495 125.755 ;
        RECT 99.645 123.165 99.905 123.180 ;
        RECT 99.645 122.885 111.465 123.165 ;
        RECT 99.645 122.860 99.905 122.885 ;
        RECT 54.960 103.315 56.255 113.770 ;
        RECT 111.225 106.305 111.465 122.885 ;
        RECT 112.235 108.335 112.490 125.435 ;
        RECT 112.230 108.015 112.490 108.335 ;
        RECT 111.215 105.985 111.475 106.305 ;
        RECT 112.235 106.260 112.490 108.015 ;
        RECT 112.235 105.940 112.495 106.260 ;
        RECT 67.710 103.165 84.830 104.065 ;
        RECT 103.830 92.575 104.090 92.585 ;
        RECT 102.690 92.285 104.090 92.575 ;
        RECT 102.690 81.085 102.960 92.285 ;
        RECT 103.830 92.265 104.090 92.285 ;
        RECT 98.750 80.750 102.960 81.085 ;
        RECT 48.495 71.270 50.625 72.535 ;
      LAYER met3 ;
        RECT 1.685 209.790 56.170 211.770 ;
        RECT 55.840 209.770 56.170 209.790 ;
        RECT 4.920 206.880 5.240 206.890 ;
        RECT 59.410 206.880 60.535 223.725 ;
        RECT 4.920 204.900 64.720 206.880 ;
        RECT 19.590 178.110 45.390 198.910 ;
        RECT 43.580 175.950 45.390 178.110 ;
        RECT 19.590 155.150 45.390 175.950 ;
        RECT 49.840 174.465 88.480 174.795 ;
        RECT 49.840 174.415 50.160 174.465 ;
        RECT 42.820 152.525 43.950 155.150 ;
        RECT 88.150 140.190 88.485 168.390 ;
        RECT 135.545 147.420 135.865 224.380 ;
        RECT 138.305 148.460 138.625 224.380 ;
        RECT 138.295 148.130 138.625 148.460 ;
        RECT 135.540 147.090 135.870 147.420 ;
        RECT 88.150 139.805 128.545 140.190 ;
        RECT 49.555 130.405 51.175 132.465 ;
        RECT 38.270 124.515 39.400 127.605 ;
        RECT 42.820 121.380 43.950 127.605 ;
        RECT 19.460 90.580 45.260 121.380 ;
        RECT 54.960 101.570 56.260 103.845 ;
        RECT 50.280 71.265 59.470 72.535 ;
        RECT 58.315 66.190 59.470 71.265 ;
        RECT 128.120 70.865 128.545 139.805 ;
        RECT 151.805 136.645 152.710 147.085 ;
        RECT 103.000 70.410 128.545 70.865 ;
        RECT 50.560 63.575 104.970 66.190 ;
        RECT 50.560 45.390 76.360 63.575 ;
        RECT 79.170 45.390 104.970 63.575 ;
        RECT 50.560 43.230 52.695 45.390 ;
        RECT 102.435 43.230 104.970 45.390 ;
        RECT 50.560 24.885 76.360 43.230 ;
        RECT 79.170 24.885 104.970 43.230 ;
        RECT 50.560 22.430 104.970 24.885 ;
      LAYER met4 ;
        RECT 30.670 224.455 91.690 224.760 ;
        RECT 59.410 223.700 60.535 224.455 ;
        RECT 59.405 223.370 60.535 223.700 ;
        RECT 59.410 223.345 60.535 223.370 ;
        RECT 94.150 222.835 94.450 224.760 ;
        RECT 135.550 224.355 135.850 224.760 ;
        RECT 138.310 224.355 138.610 224.760 ;
        RECT 135.540 224.025 135.870 224.355 ;
        RECT 138.300 224.025 138.630 224.355 ;
        RECT 143.830 222.835 144.130 224.760 ;
        RECT 94.150 222.405 144.130 222.835 ;
        RECT 20.290 178.810 44.690 198.210 ;
        RECT 20.295 175.250 21.945 178.810 ;
        RECT 20.290 174.770 44.690 175.250 ;
        RECT 20.290 174.440 50.165 174.770 ;
        RECT 20.290 155.850 44.690 174.440 ;
        RECT 38.270 120.680 39.400 124.870 ;
        RECT 20.160 91.280 44.560 120.680 ;
        RECT 49.555 82.295 51.180 130.835 ;
        RECT 36.700 80.940 51.180 82.295 ;
        RECT 36.700 9.895 37.925 80.940 ;
        RECT 54.960 77.135 56.260 102.025 ;
        RECT 44.555 75.920 56.260 77.135 ;
        RECT 44.555 14.985 46.055 75.920 ;
        RECT 103.000 65.490 103.425 70.775 ;
        RECT 51.260 48.740 75.660 65.490 ;
        RECT 79.870 48.740 104.270 65.490 ;
        RECT 51.260 46.090 104.270 48.740 ;
        RECT 71.960 42.530 75.660 46.090 ;
        RECT 79.870 42.530 83.185 46.090 ;
        RECT 51.260 39.390 104.270 42.530 ;
        RECT 51.260 23.130 75.660 39.390 ;
        RECT 79.870 23.130 104.270 39.390 ;
        RECT 44.555 13.615 133.390 14.985 ;
        RECT 36.700 8.565 114.070 9.895 ;
        RECT 113.170 1.000 114.070 8.565 ;
        RECT 132.495 1.000 133.390 13.615 ;
        RECT 151.805 1.000 152.710 137.150 ;
  END
END tt_um_analog_atenfyr1
END LIBRARY

